VERSION 5.7 ;
  NOWIREEXTENSIONATPIN ON ;
  DIVIDERCHAR "/" ;
  BUSBITCHARS "[]" ;
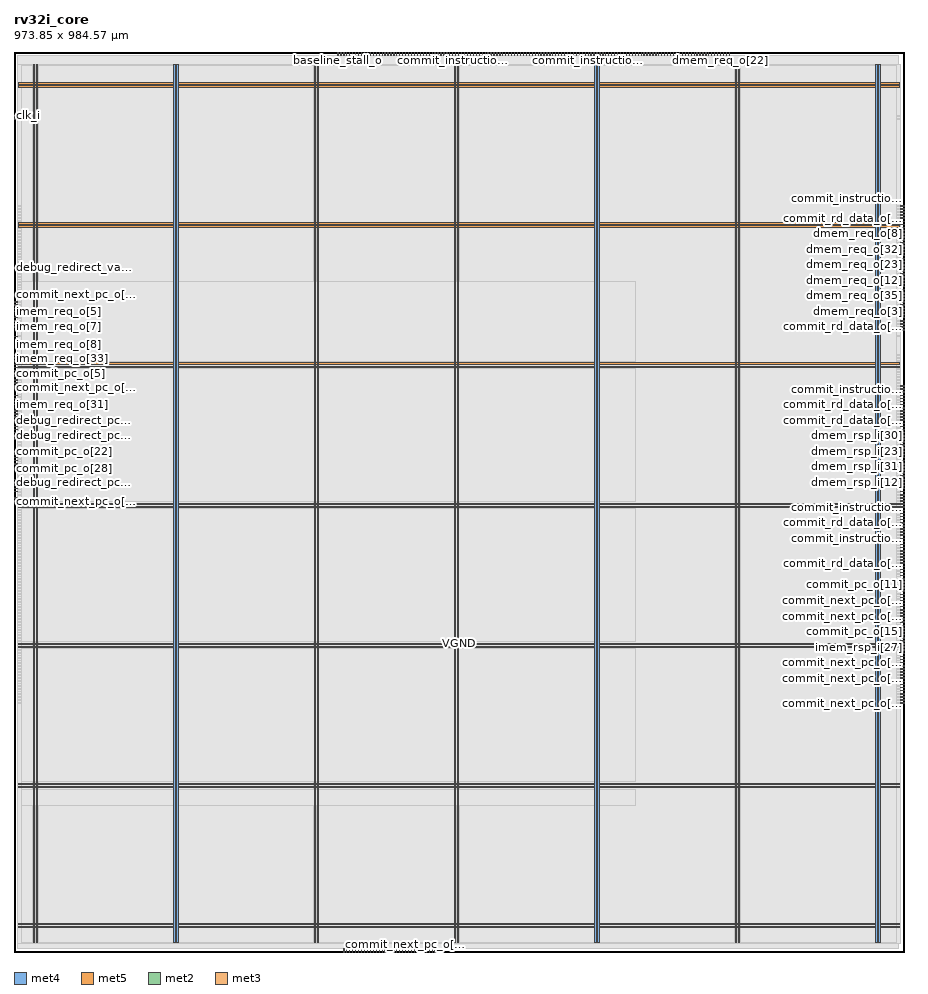
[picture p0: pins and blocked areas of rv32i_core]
MACRO rv32i_core
  CLASS BLOCK ;
  FOREIGN rv32i_core ;
  ORIGIN 0.000 0.000 ;
  SIZE 973.850 BY 984.570 ;
  PIN VGND
    DIRECTION INOUT ;
    USE GROUND ;
    PORT
      LAYER met4 ;
        RECT 24.340 10.640 25.940 971.280 ;
    END
    PORT
      LAYER met4 ;
        RECT 177.940 10.640 179.540 971.280 ;
    END
    PORT
      LAYER met4 ;
        RECT 331.540 10.640 333.140 971.280 ;
    END
    PORT
      LAYER met4 ;
        RECT 485.140 10.640 486.740 971.280 ;
    END
    PORT
      LAYER met4 ;
        RECT 638.740 10.640 640.340 971.280 ;
    END
    PORT
      LAYER met4 ;
        RECT 792.340 10.640 793.940 971.280 ;
    END
    PORT
      LAYER met4 ;
        RECT 945.940 10.640 947.540 971.280 ;
    END
    PORT
      LAYER met5 ;
        RECT 5.280 30.030 968.540 31.630 ;
    END
    PORT
      LAYER met5 ;
        RECT 5.280 183.210 968.540 184.810 ;
    END
    PORT
      LAYER met5 ;
        RECT 5.280 336.390 968.540 337.990 ;
    END
    PORT
      LAYER met5 ;
        RECT 5.280 489.570 968.540 491.170 ;
    END
    PORT
      LAYER met5 ;
        RECT 5.280 642.750 968.540 644.350 ;
    END
    PORT
      LAYER met5 ;
        RECT 5.280 795.930 968.540 797.530 ;
    END
    PORT
      LAYER met5 ;
        RECT 5.280 949.110 968.540 950.710 ;
    END
  END VGND
  PIN VPWR
    DIRECTION INOUT ;
    USE POWER ;
    PORT
      LAYER met4 ;
        RECT 21.040 10.640 22.640 971.280 ;
    END
    PORT
      LAYER met4 ;
        RECT 174.640 10.640 176.240 971.280 ;
    END
    PORT
      LAYER met4 ;
        RECT 328.240 10.640 329.840 971.280 ;
    END
    PORT
      LAYER met4 ;
        RECT 481.840 10.640 483.440 971.280 ;
    END
    PORT
      LAYER met4 ;
        RECT 635.440 10.640 637.040 971.280 ;
    END
    PORT
      LAYER met4 ;
        RECT 789.040 10.640 790.640 971.280 ;
    END
    PORT
      LAYER met4 ;
        RECT 942.640 10.640 944.240 971.280 ;
    END
    PORT
      LAYER met5 ;
        RECT 5.280 26.730 968.540 28.330 ;
    END
    PORT
      LAYER met5 ;
        RECT 5.280 179.910 968.540 181.510 ;
    END
    PORT
      LAYER met5 ;
        RECT 5.280 333.090 968.540 334.690 ;
    END
    PORT
      LAYER met5 ;
        RECT 5.280 486.270 968.540 487.870 ;
    END
    PORT
      LAYER met5 ;
        RECT 5.280 639.450 968.540 641.050 ;
    END
    PORT
      LAYER met5 ;
        RECT 5.280 792.630 968.540 794.230 ;
    END
    PORT
      LAYER met5 ;
        RECT 5.280 945.810 968.540 947.410 ;
    END
  END VPWR
  PIN baseline_stall_o
    DIRECTION OUTPUT ;
    USE SIGNAL ;
    ANTENNADIFFAREA 0.340600 ;
    PORT
      LAYER met2 ;
        RECT 354.290 980.570 354.570 984.570 ;
    END
  END baseline_stall_o
  PIN clk_i
    DIRECTION INPUT ;
    USE SIGNAL ;
    ANTENNAGATEAREA 1.286700 ;
    ANTENNADIFFAREA 0.434700 ;
    PORT
      LAYER met3 ;
        RECT 0.000 914.640 4.000 915.240 ;
    END
  END clk_i
  PIN commit_instruction_o[0]
    DIRECTION OUTPUT ;
    USE SIGNAL ;
    ANTENNADIFFAREA 0.340600 ;
    PORT
      LAYER met2 ;
        RECT 627.990 980.570 628.270 984.570 ;
    END
  END commit_instruction_o[0]
  PIN commit_instruction_o[10]
    DIRECTION OUTPUT ;
    USE SIGNAL ;
    ANTENNADIFFAREA 0.340600 ;
    PORT
      LAYER met3 ;
        RECT 969.850 615.440 973.850 616.040 ;
    END
  END commit_instruction_o[10]
  PIN commit_instruction_o[11]
    DIRECTION OUTPUT ;
    USE SIGNAL ;
    ANTENNADIFFAREA 0.340600 ;
    PORT
      LAYER met3 ;
        RECT 969.850 816.040 973.850 816.640 ;
    END
  END commit_instruction_o[11]
  PIN commit_instruction_o[12]
    DIRECTION OUTPUT ;
    USE SIGNAL ;
    ANTENNADIFFAREA 0.340600 ;
    PORT
      LAYER met2 ;
        RECT 618.330 980.570 618.610 984.570 ;
    END
  END commit_instruction_o[12]
  PIN commit_instruction_o[13]
    DIRECTION OUTPUT ;
    USE SIGNAL ;
    ANTENNADIFFAREA 0.340600 ;
    PORT
      LAYER met3 ;
        RECT 969.850 506.640 973.850 507.240 ;
    END
  END commit_instruction_o[13]
  PIN commit_instruction_o[14]
    DIRECTION OUTPUT ;
    USE SIGNAL ;
    ANTENNADIFFAREA 0.340600 ;
    PORT
      LAYER met3 ;
        RECT 969.850 496.440 973.850 497.040 ;
    END
  END commit_instruction_o[14]
  PIN commit_instruction_o[15]
    DIRECTION OUTPUT ;
    USE SIGNAL ;
    ANTENNADIFFAREA 0.340600 ;
    PORT
      LAYER met3 ;
        RECT 969.850 445.440 973.850 446.040 ;
    END
  END commit_instruction_o[15]
  PIN commit_instruction_o[16]
    DIRECTION OUTPUT ;
    USE SIGNAL ;
    ANTENNADIFFAREA 0.340600 ;
    PORT
      LAYER met3 ;
        RECT 969.850 452.240 973.850 452.840 ;
    END
  END commit_instruction_o[16]
  PIN commit_instruction_o[17]
    DIRECTION OUTPUT ;
    USE SIGNAL ;
    ANTENNADIFFAREA 0.340600 ;
    PORT
      LAYER met3 ;
        RECT 969.850 486.240 973.850 486.840 ;
    END
  END commit_instruction_o[17]
  PIN commit_instruction_o[18]
    DIRECTION OUTPUT ;
    USE SIGNAL ;
    ANTENNADIFFAREA 0.340600 ;
    PORT
      LAYER met3 ;
        RECT 969.850 431.840 973.850 432.440 ;
    END
  END commit_instruction_o[18]
  PIN commit_instruction_o[19]
    DIRECTION OUTPUT ;
    USE SIGNAL ;
    ANTENNADIFFAREA 0.340600 ;
    PORT
      LAYER met3 ;
        RECT 969.850 459.040 973.850 459.640 ;
    END
  END commit_instruction_o[19]
  PIN commit_instruction_o[1]
    DIRECTION OUTPUT ;
    USE SIGNAL ;
    ANTENNADIFFAREA 0.340600 ;
    PORT
      LAYER met2 ;
        RECT 611.890 980.570 612.170 984.570 ;
    END
  END commit_instruction_o[1]
  PIN commit_instruction_o[20]
    DIRECTION OUTPUT ;
    USE SIGNAL ;
    ANTENNADIFFAREA 0.340600 ;
    PORT
      LAYER met2 ;
        RECT 363.950 980.570 364.230 984.570 ;
    END
  END commit_instruction_o[20]
  PIN commit_instruction_o[21]
    DIRECTION OUTPUT ;
    USE SIGNAL ;
    ANTENNADIFFAREA 0.340600 ;
    PORT
      LAYER met2 ;
        RECT 547.490 980.570 547.770 984.570 ;
    END
  END commit_instruction_o[21]
  PIN commit_instruction_o[22]
    DIRECTION OUTPUT ;
    USE SIGNAL ;
    ANTENNADIFFAREA 0.340600 ;
    PORT
      LAYER met2 ;
        RECT 502.410 980.570 502.690 984.570 ;
    END
  END commit_instruction_o[22]
  PIN commit_instruction_o[23]
    DIRECTION OUTPUT ;
    USE SIGNAL ;
    ANTENNADIFFAREA 0.340600 ;
    PORT
      LAYER met2 ;
        RECT 505.630 980.570 505.910 984.570 ;
    END
  END commit_instruction_o[23]
  PIN commit_instruction_o[24]
    DIRECTION OUTPUT ;
    USE SIGNAL ;
    ANTENNADIFFAREA 0.340600 ;
    PORT
      LAYER met2 ;
        RECT 508.850 980.570 509.130 984.570 ;
    END
  END commit_instruction_o[24]
  PIN commit_instruction_o[25]
    DIRECTION OUTPUT ;
    USE SIGNAL ;
    ANTENNADIFFAREA 0.340600 ;
    PORT
      LAYER met2 ;
        RECT 380.050 980.570 380.330 984.570 ;
    END
  END commit_instruction_o[25]
  PIN commit_instruction_o[26]
    DIRECTION OUTPUT ;
    USE SIGNAL ;
    ANTENNADIFFAREA 0.340600 ;
    PORT
      LAYER met2 ;
        RECT 479.870 980.570 480.150 984.570 ;
    END
  END commit_instruction_o[26]
  PIN commit_instruction_o[27]
    DIRECTION OUTPUT ;
    USE SIGNAL ;
    ANTENNADIFFAREA 0.340600 ;
    PORT
      LAYER met2 ;
        RECT 418.690 980.570 418.970 984.570 ;
    END
  END commit_instruction_o[27]
  PIN commit_instruction_o[28]
    DIRECTION OUTPUT ;
    USE SIGNAL ;
    ANTENNADIFFAREA 0.340600 ;
    PORT
      LAYER met2 ;
        RECT 476.650 980.570 476.930 984.570 ;
    END
  END commit_instruction_o[28]
  PIN commit_instruction_o[29]
    DIRECTION OUTPUT ;
    USE SIGNAL ;
    ANTENNADIFFAREA 0.340600 ;
    PORT
      LAYER met2 ;
        RECT 444.450 980.570 444.730 984.570 ;
    END
  END commit_instruction_o[29]
  PIN commit_instruction_o[2]
    DIRECTION OUTPUT ;
    USE SIGNAL ;
    ANTENNADIFFAREA 0.340600 ;
    PORT
      LAYER met2 ;
        RECT 615.110 980.570 615.390 984.570 ;
    END
  END commit_instruction_o[2]
  PIN commit_instruction_o[30]
    DIRECTION OUTPUT ;
    USE SIGNAL ;
    ANTENNADIFFAREA 0.340600 ;
    PORT
      LAYER met2 ;
        RECT 447.670 980.570 447.950 984.570 ;
    END
  END commit_instruction_o[30]
  PIN commit_instruction_o[31]
    DIRECTION OUTPUT ;
    USE SIGNAL ;
    ANTENNADIFFAREA 0.340600 ;
    PORT
      LAYER met2 ;
        RECT 434.790 980.570 435.070 984.570 ;
    END
  END commit_instruction_o[31]
  PIN commit_instruction_o[3]
    DIRECTION OUTPUT ;
    USE SIGNAL ;
    ANTENNADIFFAREA 0.340600 ;
    PORT
      LAYER met2 ;
        RECT 483.090 980.570 483.370 984.570 ;
    END
  END commit_instruction_o[3]
  PIN commit_instruction_o[4]
    DIRECTION OUTPUT ;
    USE SIGNAL ;
    ANTENNADIFFAREA 0.340600 ;
    PORT
      LAYER met2 ;
        RECT 473.430 980.570 473.710 984.570 ;
    END
  END commit_instruction_o[4]
  PIN commit_instruction_o[5]
    DIRECTION OUTPUT ;
    USE SIGNAL ;
    ANTENNADIFFAREA 0.340600 ;
    PORT
      LAYER met2 ;
        RECT 499.190 980.570 499.470 984.570 ;
    END
  END commit_instruction_o[5]
  PIN commit_instruction_o[6]
    DIRECTION OUTPUT ;
    USE SIGNAL ;
    ANTENNADIFFAREA 0.340600 ;
    PORT
      LAYER met2 ;
        RECT 489.530 980.570 489.810 984.570 ;
    END
  END commit_instruction_o[6]
  PIN commit_instruction_o[7]
    DIRECTION OUTPUT ;
    USE SIGNAL ;
    ANTENNADIFFAREA 0.340600 ;
    PORT
      LAYER met3 ;
        RECT 969.850 775.240 973.850 775.840 ;
    END
  END commit_instruction_o[7]
  PIN commit_instruction_o[8]
    DIRECTION OUTPUT ;
    USE SIGNAL ;
    ANTENNADIFFAREA 0.340600 ;
    PORT
      LAYER met3 ;
        RECT 969.850 754.840 973.850 755.440 ;
    END
  END commit_instruction_o[8]
  PIN commit_instruction_o[9]
    DIRECTION OUTPUT ;
    USE SIGNAL ;
    ANTENNADIFFAREA 0.340600 ;
    PORT
      LAYER met3 ;
        RECT 969.850 584.840 973.850 585.440 ;
    END
  END commit_instruction_o[9]
  PIN commit_next_pc_o[0]
    DIRECTION OUTPUT ;
    USE SIGNAL ;
    ANTENNADIFFAREA 0.340600 ;
    PORT
      LAYER met2 ;
        RECT 466.990 980.570 467.270 984.570 ;
    END
  END commit_next_pc_o[0]
  PIN commit_next_pc_o[10]
    DIRECTION OUTPUT ;
    USE SIGNAL ;
    ANTENNADIFFAREA 0.340600 ;
    PORT
      LAYER met2 ;
        RECT 383.270 980.570 383.550 984.570 ;
    END
  END commit_next_pc_o[10]
  PIN commit_next_pc_o[11]
    DIRECTION OUTPUT ;
    USE SIGNAL ;
    ANTENNADIFFAREA 0.340600 ;
    PORT
      LAYER met3 ;
        RECT 969.850 272.040 973.850 272.640 ;
    END
  END commit_next_pc_o[11]
  PIN commit_next_pc_o[12]
    DIRECTION OUTPUT ;
    USE SIGNAL ;
    ANTENNADIFFAREA 0.340600 ;
    PORT
      LAYER met2 ;
        RECT 521.730 980.570 522.010 984.570 ;
    END
  END commit_next_pc_o[12]
  PIN commit_next_pc_o[13]
    DIRECTION OUTPUT ;
    USE SIGNAL ;
    ANTENNADIFFAREA 0.340600 ;
    PORT
      LAYER met2 ;
        RECT 376.830 980.570 377.110 984.570 ;
    END
  END commit_next_pc_o[13]
  PIN commit_next_pc_o[14]
    DIRECTION OUTPUT ;
    USE SIGNAL ;
    ANTENNADIFFAREA 0.340600 ;
    PORT
      LAYER met3 ;
        RECT 0.000 652.840 4.000 653.440 ;
    END
  END commit_next_pc_o[14]
  PIN commit_next_pc_o[15]
    DIRECTION OUTPUT ;
    USE SIGNAL ;
    ANTENNADIFFAREA 0.340600 ;
    PORT
      LAYER met3 ;
        RECT 969.850 275.440 973.850 276.040 ;
    END
  END commit_next_pc_o[15]
  PIN commit_next_pc_o[16]
    DIRECTION OUTPUT ;
    USE SIGNAL ;
    ANTENNADIFFAREA 0.340600 ;
    PORT
      LAYER met2 ;
        RECT 553.930 980.570 554.210 984.570 ;
    END
  END commit_next_pc_o[16]
  PIN commit_next_pc_o[17]
    DIRECTION OUTPUT ;
    USE SIGNAL ;
    ANTENNADIFFAREA 0.340600 ;
    PORT
      LAYER met2 ;
        RECT 524.950 980.570 525.230 984.570 ;
    END
  END commit_next_pc_o[17]
  PIN commit_next_pc_o[18]
    DIRECTION OUTPUT ;
    USE SIGNAL ;
    ANTENNADIFFAREA 0.340600 ;
    PORT
      LAYER met3 ;
        RECT 969.850 299.240 973.850 299.840 ;
    END
  END commit_next_pc_o[18]
  PIN commit_next_pc_o[19]
    DIRECTION OUTPUT ;
    USE SIGNAL ;
    ANTENNADIFFAREA 0.340600 ;
    PORT
      LAYER met2 ;
        RECT 428.350 0.000 428.630 4.000 ;
    END
  END commit_next_pc_o[19]
  PIN commit_next_pc_o[1]
    DIRECTION OUTPUT ;
    USE SIGNAL ;
    ANTENNADIFFAREA 0.340600 ;
    PORT
      LAYER met2 ;
        RECT 566.810 980.570 567.090 984.570 ;
    END
  END commit_next_pc_o[1]
  PIN commit_next_pc_o[20]
    DIRECTION OUTPUT ;
    USE SIGNAL ;
    ANTENNADIFFAREA 0.340600 ;
    PORT
      LAYER met2 ;
        RECT 515.290 980.570 515.570 984.570 ;
    END
  END commit_next_pc_o[20]
  PIN commit_next_pc_o[21]
    DIRECTION OUTPUT ;
    USE SIGNAL ;
    ANTENNADIFFAREA 0.340600 ;
    PORT
      LAYER met2 ;
        RECT 531.390 980.570 531.670 984.570 ;
    END
  END commit_next_pc_o[21]
  PIN commit_next_pc_o[22]
    DIRECTION OUTPUT ;
    USE SIGNAL ;
    ANTENNADIFFAREA 0.340600 ;
    PORT
      LAYER met2 ;
        RECT 389.710 980.570 389.990 984.570 ;
    END
  END commit_next_pc_o[22]
  PIN commit_next_pc_o[23]
    DIRECTION OUTPUT ;
    USE SIGNAL ;
    ANTENNADIFFAREA 0.340600 ;
    PORT
      LAYER met2 ;
        RECT 592.570 980.570 592.850 984.570 ;
    END
  END commit_next_pc_o[23]
  PIN commit_next_pc_o[24]
    DIRECTION OUTPUT ;
    USE SIGNAL ;
    ANTENNADIFFAREA 0.340600 ;
    PORT
      LAYER met2 ;
        RECT 425.130 980.570 425.410 984.570 ;
    END
  END commit_next_pc_o[24]
  PIN commit_next_pc_o[25]
    DIRECTION OUTPUT ;
    USE SIGNAL ;
    ANTENNADIFFAREA 0.340600 ;
    PORT
      LAYER met3 ;
        RECT 0.000 710.640 4.000 711.240 ;
    END
  END commit_next_pc_o[25]
  PIN commit_next_pc_o[26]
    DIRECTION OUTPUT ;
    USE SIGNAL ;
    ANTENNADIFFAREA 0.340600 ;
    PORT
      LAYER met3 ;
        RECT 969.850 316.240 973.850 316.840 ;
    END
  END commit_next_pc_o[26]
  PIN commit_next_pc_o[27]
    DIRECTION OUTPUT ;
    USE SIGNAL ;
    ANTENNADIFFAREA 0.340600 ;
    PORT
      LAYER met2 ;
        RECT 454.110 980.570 454.390 984.570 ;
    END
  END commit_next_pc_o[27]
  PIN commit_next_pc_o[28]
    DIRECTION OUTPUT ;
    USE SIGNAL ;
    ANTENNADIFFAREA 0.340600 ;
    PORT
      LAYER met2 ;
        RECT 367.170 980.570 367.450 984.570 ;
    END
  END commit_next_pc_o[28]
  PIN commit_next_pc_o[29]
    DIRECTION OUTPUT ;
    USE SIGNAL ;
    ANTENNADIFFAREA 0.340600 ;
    PORT
      LAYER met3 ;
        RECT 969.850 346.840 973.850 347.440 ;
    END
  END commit_next_pc_o[29]
  PIN commit_next_pc_o[2]
    DIRECTION OUTPUT ;
    USE SIGNAL ;
    ANTENNADIFFAREA 0.340600 ;
    PORT
      LAYER met3 ;
        RECT 969.850 306.040 973.850 306.640 ;
    END
  END commit_next_pc_o[2]
  PIN commit_next_pc_o[30]
    DIRECTION OUTPUT ;
    USE SIGNAL ;
    ANTENNADIFFAREA 0.340600 ;
    PORT
      LAYER met2 ;
        RECT 541.050 980.570 541.330 984.570 ;
    END
  END commit_next_pc_o[30]
  PIN commit_next_pc_o[31]
    DIRECTION OUTPUT ;
    USE SIGNAL ;
    ANTENNADIFFAREA 0.340600 ;
    PORT
      LAYER met3 ;
        RECT 969.850 367.240 973.850 367.840 ;
    END
  END commit_next_pc_o[31]
  PIN commit_next_pc_o[3]
    DIRECTION OUTPUT ;
    USE SIGNAL ;
    ANTENNADIFFAREA 0.340600 ;
    PORT
      LAYER met3 ;
        RECT 0.000 493.040 4.000 493.640 ;
    END
  END commit_next_pc_o[3]
  PIN commit_next_pc_o[4]
    DIRECTION OUTPUT ;
    USE SIGNAL ;
    ANTENNADIFFAREA 0.340600 ;
    PORT
      LAYER met2 ;
        RECT 560.370 980.570 560.650 984.570 ;
    END
  END commit_next_pc_o[4]
  PIN commit_next_pc_o[5]
    DIRECTION OUTPUT ;
    USE SIGNAL ;
    ANTENNADIFFAREA 0.340600 ;
    PORT
      LAYER met3 ;
        RECT 969.850 472.640 973.850 473.240 ;
    END
  END commit_next_pc_o[5]
  PIN commit_next_pc_o[6]
    DIRECTION OUTPUT ;
    USE SIGNAL ;
    ANTENNADIFFAREA 0.340600 ;
    PORT
      LAYER met2 ;
        RECT 392.930 980.570 393.210 984.570 ;
    END
  END commit_next_pc_o[6]
  PIN commit_next_pc_o[7]
    DIRECTION OUTPUT ;
    USE SIGNAL ;
    ANTENNADIFFAREA 0.340600 ;
    PORT
      LAYER met3 ;
        RECT 0.000 608.640 4.000 609.240 ;
    END
  END commit_next_pc_o[7]
  PIN commit_next_pc_o[8]
    DIRECTION OUTPUT ;
    USE SIGNAL ;
    ANTENNADIFFAREA 0.340600 ;
    PORT
      LAYER met3 ;
        RECT 969.850 384.240 973.850 384.840 ;
    END
  END commit_next_pc_o[8]
  PIN commit_next_pc_o[9]
    DIRECTION OUTPUT ;
    USE SIGNAL ;
    ANTENNADIFFAREA 0.340600 ;
    PORT
      LAYER met3 ;
        RECT 0.000 690.240 4.000 690.840 ;
    END
  END commit_next_pc_o[9]
  PIN commit_pc_o[0]
    DIRECTION OUTPUT ;
    USE SIGNAL ;
    ANTENNADIFFAREA 0.340600 ;
    PORT
      LAYER met2 ;
        RECT 650.530 980.570 650.810 984.570 ;
    END
  END commit_pc_o[0]
  PIN commit_pc_o[10]
    DIRECTION OUTPUT ;
    USE SIGNAL ;
    ANTENNADIFFAREA 0.340600 ;
    PORT
      LAYER met3 ;
        RECT 969.850 374.040 973.850 374.640 ;
    END
  END commit_pc_o[10]
  PIN commit_pc_o[11]
    DIRECTION OUTPUT ;
    USE SIGNAL ;
    ANTENNADIFFAREA 0.340600 ;
    PORT
      LAYER met3 ;
        RECT 969.850 401.240 973.850 401.840 ;
    END
  END commit_pc_o[11]
  PIN commit_pc_o[12]
    DIRECTION OUTPUT ;
    USE SIGNAL ;
    ANTENNADIFFAREA 0.340600 ;
    PORT
      LAYER met3 ;
        RECT 969.850 448.840 973.850 449.440 ;
    END
  END commit_pc_o[12]
  PIN commit_pc_o[13]
    DIRECTION OUTPUT ;
    USE SIGNAL ;
    ANTENNADIFFAREA 0.340600 ;
    PORT
      LAYER met2 ;
        RECT 454.110 0.000 454.390 4.000 ;
    END
  END commit_pc_o[13]
  PIN commit_pc_o[14]
    DIRECTION OUTPUT ;
    USE SIGNAL ;
    ANTENNADIFFAREA 0.340600 ;
    PORT
      LAYER met3 ;
        RECT 969.850 465.840 973.850 466.440 ;
    END
  END commit_pc_o[14]
  PIN commit_pc_o[15]
    DIRECTION OUTPUT ;
    USE SIGNAL ;
    ANTENNADIFFAREA 0.340600 ;
    PORT
      LAYER met3 ;
        RECT 969.850 350.240 973.850 350.840 ;
    END
  END commit_pc_o[15]
  PIN commit_pc_o[16]
    DIRECTION OUTPUT ;
    USE SIGNAL ;
    ANTENNADIFFAREA 0.340600 ;
    PORT
      LAYER met3 ;
        RECT 969.850 357.040 973.850 357.640 ;
    END
  END commit_pc_o[16]
  PIN commit_pc_o[17]
    DIRECTION OUTPUT ;
    USE SIGNAL ;
    ANTENNADIFFAREA 0.340600 ;
    PORT
      LAYER met3 ;
        RECT 969.850 391.040 973.850 391.640 ;
    END
  END commit_pc_o[17]
  PIN commit_pc_o[18]
    DIRECTION OUTPUT ;
    USE SIGNAL ;
    ANTENNADIFFAREA 0.340600 ;
    PORT
      LAYER met3 ;
        RECT 969.850 387.640 973.850 388.240 ;
    END
  END commit_pc_o[18]
  PIN commit_pc_o[19]
    DIRECTION OUTPUT ;
    USE SIGNAL ;
    ANTENNADIFFAREA 0.340600 ;
    PORT
      LAYER met3 ;
        RECT 969.850 302.640 973.850 303.240 ;
    END
  END commit_pc_o[19]
  PIN commit_pc_o[1]
    DIRECTION OUTPUT ;
    USE SIGNAL ;
    ANTENNADIFFAREA 0.340600 ;
    PORT
      LAYER met2 ;
        RECT 599.010 980.570 599.290 984.570 ;
    END
  END commit_pc_o[1]
  PIN commit_pc_o[20]
    DIRECTION OUTPUT ;
    USE SIGNAL ;
    ANTENNADIFFAREA 0.340600 ;
    PORT
      LAYER met3 ;
        RECT 0.000 506.640 4.000 507.240 ;
    END
  END commit_pc_o[20]
  PIN commit_pc_o[21]
    DIRECTION OUTPUT ;
    USE SIGNAL ;
    ANTENNADIFFAREA 0.340600 ;
    PORT
      LAYER met3 ;
        RECT 0.000 567.840 4.000 568.440 ;
    END
  END commit_pc_o[21]
  PIN commit_pc_o[22]
    DIRECTION OUTPUT ;
    USE SIGNAL ;
    ANTENNADIFFAREA 0.340600 ;
    PORT
      LAYER met3 ;
        RECT 0.000 547.440 4.000 548.040 ;
    END
  END commit_pc_o[22]
  PIN commit_pc_o[23]
    DIRECTION OUTPUT ;
    USE SIGNAL ;
    ANTENNADIFFAREA 0.340600 ;
    PORT
      LAYER met3 ;
        RECT 969.850 360.440 973.850 361.040 ;
    END
  END commit_pc_o[23]
  PIN commit_pc_o[24]
    DIRECTION OUTPUT ;
    USE SIGNAL ;
    ANTENNADIFFAREA 0.340600 ;
    PORT
      LAYER met3 ;
        RECT 0.000 496.440 4.000 497.040 ;
    END
  END commit_pc_o[24]
  PIN commit_pc_o[25]
    DIRECTION OUTPUT ;
    USE SIGNAL ;
    ANTENNADIFFAREA 0.340600 ;
    PORT
      LAYER met3 ;
        RECT 0.000 533.840 4.000 534.440 ;
    END
  END commit_pc_o[25]
  PIN commit_pc_o[26]
    DIRECTION OUTPUT ;
    USE SIGNAL ;
    ANTENNADIFFAREA 0.340600 ;
    PORT
      LAYER met2 ;
        RECT 444.450 0.000 444.730 4.000 ;
    END
  END commit_pc_o[26]
  PIN commit_pc_o[27]
    DIRECTION OUTPUT ;
    USE SIGNAL ;
    ANTENNADIFFAREA 0.340600 ;
    PORT
      LAYER met3 ;
        RECT 0.000 516.840 4.000 517.440 ;
    END
  END commit_pc_o[27]
  PIN commit_pc_o[28]
    DIRECTION OUTPUT ;
    USE SIGNAL ;
    ANTENNADIFFAREA 0.340600 ;
    PORT
      LAYER met3 ;
        RECT 0.000 537.240 4.000 537.840 ;
    END
  END commit_pc_o[28]
  PIN commit_pc_o[29]
    DIRECTION OUTPUT ;
    USE SIGNAL ;
    ANTENNADIFFAREA 0.340600 ;
    PORT
      LAYER met3 ;
        RECT 969.850 397.840 973.850 398.440 ;
    END
  END commit_pc_o[29]
  PIN commit_pc_o[2]
    DIRECTION OUTPUT ;
    USE SIGNAL ;
    ANTENNADIFFAREA 0.340600 ;
    PORT
      LAYER met2 ;
        RECT 470.210 980.570 470.490 984.570 ;
    END
  END commit_pc_o[2]
  PIN commit_pc_o[30]
    DIRECTION OUTPUT ;
    USE SIGNAL ;
    ANTENNADIFFAREA 0.340600 ;
    PORT
      LAYER met3 ;
        RECT 0.000 601.840 4.000 602.440 ;
    END
  END commit_pc_o[30]
  PIN commit_pc_o[31]
    DIRECTION OUTPUT ;
    USE SIGNAL ;
    ANTENNADIFFAREA 0.340600 ;
    PORT
      LAYER met2 ;
        RECT 457.330 0.000 457.610 4.000 ;
    END
  END commit_pc_o[31]
  PIN commit_pc_o[3]
    DIRECTION OUTPUT ;
    USE SIGNAL ;
    ANTENNADIFFAREA 0.340600 ;
    PORT
      LAYER met3 ;
        RECT 0.000 646.040 4.000 646.640 ;
    END
  END commit_pc_o[3]
  PIN commit_pc_o[4]
    DIRECTION OUTPUT ;
    USE SIGNAL ;
    ANTENNADIFFAREA 0.340600 ;
    PORT
      LAYER met3 ;
        RECT 0.000 639.240 4.000 639.840 ;
    END
  END commit_pc_o[4]
  PIN commit_pc_o[5]
    DIRECTION OUTPUT ;
    USE SIGNAL ;
    ANTENNADIFFAREA 0.340600 ;
    PORT
      LAYER met3 ;
        RECT 0.000 632.440 4.000 633.040 ;
    END
  END commit_pc_o[5]
  PIN commit_pc_o[6]
    DIRECTION OUTPUT ;
    USE SIGNAL ;
    ANTENNADIFFAREA 0.340600 ;
    PORT
      LAYER met3 ;
        RECT 0.000 635.840 4.000 636.440 ;
    END
  END commit_pc_o[6]
  PIN commit_pc_o[7]
    DIRECTION OUTPUT ;
    USE SIGNAL ;
    ANTENNADIFFAREA 0.340600 ;
    PORT
      LAYER met3 ;
        RECT 0.000 642.640 4.000 643.240 ;
    END
  END commit_pc_o[7]
  PIN commit_pc_o[8]
    DIRECTION OUTPUT ;
    USE SIGNAL ;
    ANTENNADIFFAREA 0.340600 ;
    PORT
      LAYER met3 ;
        RECT 969.850 377.440 973.850 378.040 ;
    END
  END commit_pc_o[8]
  PIN commit_pc_o[9]
    DIRECTION OUTPUT ;
    USE SIGNAL ;
    ANTENNADIFFAREA 0.340600 ;
    PORT
      LAYER met3 ;
        RECT 969.850 394.440 973.850 395.040 ;
    END
  END commit_pc_o[9]
  PIN commit_rd_data_o[0]
    DIRECTION OUTPUT ;
    USE SIGNAL ;
    ANTENNADIFFAREA 0.340600 ;
    PORT
      LAYER met3 ;
        RECT 969.850 802.440 973.850 803.040 ;
    END
  END commit_rd_data_o[0]
  PIN commit_rd_data_o[10]
    DIRECTION OUTPUT ;
    USE SIGNAL ;
    ANTENNADIFFAREA 0.340600 ;
    PORT
      LAYER met3 ;
        RECT 969.850 601.840 973.850 602.440 ;
    END
  END commit_rd_data_o[10]
  PIN commit_rd_data_o[11]
    DIRECTION OUTPUT ;
    USE SIGNAL ;
    ANTENNADIFFAREA 0.340600 ;
    PORT
      LAYER met3 ;
        RECT 969.850 289.040 973.850 289.640 ;
    END
  END commit_rd_data_o[11]
  PIN commit_rd_data_o[12]
    DIRECTION OUTPUT ;
    USE SIGNAL ;
    ANTENNADIFFAREA 0.340600 ;
    PORT
      LAYER met3 ;
        RECT 969.850 595.040 973.850 595.640 ;
    END
  END commit_rd_data_o[12]
  PIN commit_rd_data_o[13]
    DIRECTION OUTPUT ;
    USE SIGNAL ;
    ANTENNADIFFAREA 0.340600 ;
    PORT
      LAYER met3 ;
        RECT 969.850 295.840 973.850 296.440 ;
    END
  END commit_rd_data_o[13]
  PIN commit_rd_data_o[14]
    DIRECTION OUTPUT ;
    USE SIGNAL ;
    ANTENNADIFFAREA 0.340600 ;
    PORT
      LAYER met3 ;
        RECT 969.850 425.040 973.850 425.640 ;
    END
  END commit_rd_data_o[14]
  PIN commit_rd_data_o[15]
    DIRECTION OUTPUT ;
    USE SIGNAL ;
    ANTENNADIFFAREA 0.340600 ;
    PORT
      LAYER met3 ;
        RECT 969.850 455.640 973.850 456.240 ;
    END
  END commit_rd_data_o[15]
  PIN commit_rd_data_o[16]
    DIRECTION OUTPUT ;
    USE SIGNAL ;
    ANTENNADIFFAREA 0.340600 ;
    PORT
      LAYER met3 ;
        RECT 969.850 411.440 973.850 412.040 ;
    END
  END commit_rd_data_o[16]
  PIN commit_rd_data_o[17]
    DIRECTION OUTPUT ;
    USE SIGNAL ;
    ANTENNADIFFAREA 0.340600 ;
    PORT
      LAYER met3 ;
        RECT 969.850 795.640 973.850 796.240 ;
    END
  END commit_rd_data_o[17]
  PIN commit_rd_data_o[18]
    DIRECTION OUTPUT ;
    USE SIGNAL ;
    ANTENNADIFFAREA 0.340600 ;
    PORT
      LAYER met3 ;
        RECT 969.850 799.040 973.850 799.640 ;
    END
  END commit_rd_data_o[18]
  PIN commit_rd_data_o[19]
    DIRECTION OUTPUT ;
    USE SIGNAL ;
    ANTENNADIFFAREA 0.340600 ;
    PORT
      LAYER met3 ;
        RECT 969.850 581.440 973.850 582.040 ;
    END
  END commit_rd_data_o[19]
  PIN commit_rd_data_o[1]
    DIRECTION OUTPUT ;
    USE SIGNAL ;
    ANTENNADIFFAREA 0.340600 ;
    PORT
      LAYER met3 ;
        RECT 969.850 792.240 973.850 792.840 ;
    END
  END commit_rd_data_o[1]
  PIN commit_rd_data_o[20]
    DIRECTION OUTPUT ;
    USE SIGNAL ;
    ANTENNADIFFAREA 0.340600 ;
    PORT
      LAYER met3 ;
        RECT 969.850 809.240 973.850 809.840 ;
    END
  END commit_rd_data_o[20]
  PIN commit_rd_data_o[21]
    DIRECTION OUTPUT ;
    USE SIGNAL ;
    ANTENNADIFFAREA 0.340600 ;
    PORT
      LAYER met3 ;
        RECT 969.850 489.640 973.850 490.240 ;
    END
  END commit_rd_data_o[21]
  PIN commit_rd_data_o[22]
    DIRECTION OUTPUT ;
    USE SIGNAL ;
    ANTENNADIFFAREA 0.340600 ;
    PORT
      LAYER met3 ;
        RECT 969.850 421.640 973.850 422.240 ;
    END
  END commit_rd_data_o[22]
  PIN commit_rd_data_o[23]
    DIRECTION OUTPUT ;
    USE SIGNAL ;
    ANTENNADIFFAREA 0.340600 ;
    PORT
      LAYER met3 ;
        RECT 969.850 278.840 973.850 279.440 ;
    END
  END commit_rd_data_o[23]
  PIN commit_rd_data_o[24]
    DIRECTION OUTPUT ;
    USE SIGNAL ;
    ANTENNADIFFAREA 0.340600 ;
    PORT
      LAYER met3 ;
        RECT 969.850 363.840 973.850 364.440 ;
    END
  END commit_rd_data_o[24]
  PIN commit_rd_data_o[25]
    DIRECTION OUTPUT ;
    USE SIGNAL ;
    ANTENNADIFFAREA 0.340600 ;
    PORT
      LAYER met3 ;
        RECT 969.850 744.640 973.850 745.240 ;
    END
  END commit_rd_data_o[25]
  PIN commit_rd_data_o[26]
    DIRECTION OUTPUT ;
    USE SIGNAL ;
    ANTENNADIFFAREA 0.340600 ;
    PORT
      LAYER met3 ;
        RECT 969.850 782.040 973.850 782.640 ;
    END
  END commit_rd_data_o[26]
  PIN commit_rd_data_o[27]
    DIRECTION OUTPUT ;
    USE SIGNAL ;
    ANTENNADIFFAREA 0.340600 ;
    PORT
      LAYER met3 ;
        RECT 969.850 540.640 973.850 541.240 ;
    END
  END commit_rd_data_o[27]
  PIN commit_rd_data_o[28]
    DIRECTION OUTPUT ;
    USE SIGNAL ;
    ANTENNADIFFAREA 0.340600 ;
    PORT
      LAYER met3 ;
        RECT 969.850 418.240 973.850 418.840 ;
    END
  END commit_rd_data_o[28]
  PIN commit_rd_data_o[29]
    DIRECTION OUTPUT ;
    USE SIGNAL ;
    ANTENNADIFFAREA 0.340600 ;
    PORT
      LAYER met3 ;
        RECT 969.850 778.640 973.850 779.240 ;
    END
  END commit_rd_data_o[29]
  PIN commit_rd_data_o[2]
    DIRECTION OUTPUT ;
    USE SIGNAL ;
    ANTENNADIFFAREA 0.340600 ;
    PORT
      LAYER met3 ;
        RECT 969.850 683.440 973.850 684.040 ;
    END
  END commit_rd_data_o[2]
  PIN commit_rd_data_o[30]
    DIRECTION OUTPUT ;
    USE SIGNAL ;
    ANTENNADIFFAREA 0.340600 ;
    PORT
      LAYER met3 ;
        RECT 969.850 442.040 973.850 442.640 ;
    END
  END commit_rd_data_o[30]
  PIN commit_rd_data_o[31]
    DIRECTION OUTPUT ;
    USE SIGNAL ;
    ANTENNADIFFAREA 0.340600 ;
    PORT
      LAYER met3 ;
        RECT 969.850 285.640 973.850 286.240 ;
    END
  END commit_rd_data_o[31]
  PIN commit_rd_data_o[3]
    DIRECTION OUTPUT ;
    USE SIGNAL ;
    ANTENNADIFFAREA 0.340600 ;
    PORT
      LAYER met3 ;
        RECT 969.850 510.040 973.850 510.640 ;
    END
  END commit_rd_data_o[3]
  PIN commit_rd_data_o[4]
    DIRECTION OUTPUT ;
    USE SIGNAL ;
    ANTENNADIFFAREA 0.340600 ;
    PORT
      LAYER met3 ;
        RECT 969.850 612.040 973.850 612.640 ;
    END
  END commit_rd_data_o[4]
  PIN commit_rd_data_o[5]
    DIRECTION OUTPUT ;
    USE SIGNAL ;
    ANTENNADIFFAREA 0.340600 ;
    PORT
      LAYER met3 ;
        RECT 969.850 282.240 973.850 282.840 ;
    END
  END commit_rd_data_o[5]
  PIN commit_rd_data_o[6]
    DIRECTION OUTPUT ;
    USE SIGNAL ;
    ANTENNADIFFAREA 0.340600 ;
    PORT
      LAYER met3 ;
        RECT 969.850 309.440 973.850 310.040 ;
    END
  END commit_rd_data_o[6]
  PIN commit_rd_data_o[7]
    DIRECTION OUTPUT ;
    USE SIGNAL ;
    ANTENNADIFFAREA 0.340600 ;
    PORT
      LAYER met3 ;
        RECT 969.850 469.240 973.850 469.840 ;
    END
  END commit_rd_data_o[7]
  PIN commit_rd_data_o[8]
    DIRECTION OUTPUT ;
    USE SIGNAL ;
    ANTENNADIFFAREA 0.340600 ;
    PORT
      LAYER met3 ;
        RECT 969.850 741.240 973.850 741.840 ;
    END
  END commit_rd_data_o[8]
  PIN commit_rd_data_o[9]
    DIRECTION OUTPUT ;
    USE SIGNAL ;
    ANTENNADIFFAREA 0.340600 ;
    PORT
      LAYER met3 ;
        RECT 969.850 598.440 973.850 599.040 ;
    END
  END commit_rd_data_o[9]
  PIN commit_rd_index_o[0]
    DIRECTION OUTPUT ;
    USE SIGNAL ;
    ANTENNADIFFAREA 0.340600 ;
    PORT
      LAYER met3 ;
        RECT 969.850 727.640 973.850 728.240 ;
    END
  END commit_rd_index_o[0]
  PIN commit_rd_index_o[1]
    DIRECTION OUTPUT ;
    USE SIGNAL ;
    ANTENNADIFFAREA 0.340600 ;
    PORT
      LAYER met3 ;
        RECT 969.850 693.640 973.850 694.240 ;
    END
  END commit_rd_index_o[1]
  PIN commit_rd_index_o[2]
    DIRECTION OUTPUT ;
    USE SIGNAL ;
    ANTENNADIFFAREA 0.340600 ;
    PORT
      LAYER met3 ;
        RECT 969.850 578.040 973.850 578.640 ;
    END
  END commit_rd_index_o[2]
  PIN commit_rd_index_o[3]
    DIRECTION OUTPUT ;
    USE SIGNAL ;
    ANTENNADIFFAREA 0.340600 ;
    PORT
      LAYER met3 ;
        RECT 969.850 588.240 973.850 588.840 ;
    END
  END commit_rd_index_o[3]
  PIN commit_rd_index_o[4]
    DIRECTION OUTPUT ;
    USE SIGNAL ;
    ANTENNADIFFAREA 0.340600 ;
    PORT
      LAYER met3 ;
        RECT 969.850 758.240 973.850 758.840 ;
    END
  END commit_rd_index_o[4]
  PIN commit_rd_write_o
    DIRECTION OUTPUT ;
    USE SIGNAL ;
    ANTENNADIFFAREA 0.340600 ;
    PORT
      LAYER met3 ;
        RECT 969.850 788.840 973.850 789.440 ;
    END
  END commit_rd_write_o
  PIN commit_trap_o
    DIRECTION OUTPUT ;
    USE SIGNAL ;
    ANTENNADIFFAREA 0.340600 ;
    PORT
      LAYER met2 ;
        RECT 386.490 980.570 386.770 984.570 ;
    END
  END commit_trap_o
  PIN commit_valid_o
    DIRECTION OUTPUT ;
    USE SIGNAL ;
    ANTENNADIFFAREA 0.340600 ;
    PORT
      LAYER met2 ;
        RECT 405.810 980.570 406.090 984.570 ;
    END
  END commit_valid_o
  PIN debug_redirect_pc_o[0]
    DIRECTION OUTPUT ;
    USE SIGNAL ;
    ANTENNADIFFAREA 0.340600 ;
    PORT
      LAYER met3 ;
        RECT 0.000 686.840 4.000 687.440 ;
    END
  END debug_redirect_pc_o[0]
  PIN debug_redirect_pc_o[10]
    DIRECTION OUTPUT ;
    USE SIGNAL ;
    ANTENNADIFFAREA 0.340600 ;
    PORT
      LAYER met3 ;
        RECT 969.850 438.640 973.850 439.240 ;
    END
  END debug_redirect_pc_o[10]
  PIN debug_redirect_pc_o[11]
    DIRECTION OUTPUT ;
    USE SIGNAL ;
    ANTENNADIFFAREA 0.340600 ;
    PORT
      LAYER met3 ;
        RECT 969.850 435.240 973.850 435.840 ;
    END
  END debug_redirect_pc_o[11]
  PIN debug_redirect_pc_o[12]
    DIRECTION OUTPUT ;
    USE SIGNAL ;
    ANTENNADIFFAREA 0.340600 ;
    PORT
      LAYER met2 ;
        RECT 396.150 0.000 396.430 4.000 ;
    END
  END debug_redirect_pc_o[12]
  PIN debug_redirect_pc_o[13]
    DIRECTION OUTPUT ;
    USE SIGNAL ;
    ANTENNADIFFAREA 0.340600 ;
    PORT
      LAYER met2 ;
        RECT 399.370 0.000 399.650 4.000 ;
    END
  END debug_redirect_pc_o[13]
  PIN debug_redirect_pc_o[14]
    DIRECTION OUTPUT ;
    USE SIGNAL ;
    ANTENNADIFFAREA 0.340600 ;
    PORT
      LAYER met3 ;
        RECT 969.850 479.440 973.850 480.040 ;
    END
  END debug_redirect_pc_o[14]
  PIN debug_redirect_pc_o[15]
    DIRECTION OUTPUT ;
    USE SIGNAL ;
    ANTENNADIFFAREA 0.340600 ;
    PORT
      LAYER met2 ;
        RECT 409.030 0.000 409.310 4.000 ;
    END
  END debug_redirect_pc_o[15]
  PIN debug_redirect_pc_o[16]
    DIRECTION OUTPUT ;
    USE SIGNAL ;
    ANTENNADIFFAREA 0.340600 ;
    PORT
      LAYER met3 ;
        RECT 969.850 414.840 973.850 415.440 ;
    END
  END debug_redirect_pc_o[16]
  PIN debug_redirect_pc_o[17]
    DIRECTION OUTPUT ;
    USE SIGNAL ;
    ANTENNADIFFAREA 0.340600 ;
    PORT
      LAYER met2 ;
        RECT 425.130 0.000 425.410 4.000 ;
    END
  END debug_redirect_pc_o[17]
  PIN debug_redirect_pc_o[18]
    DIRECTION OUTPUT ;
    USE SIGNAL ;
    ANTENNADIFFAREA 0.340600 ;
    PORT
      LAYER met3 ;
        RECT 969.850 404.640 973.850 405.240 ;
    END
  END debug_redirect_pc_o[18]
  PIN debug_redirect_pc_o[19]
    DIRECTION OUTPUT ;
    USE SIGNAL ;
    ANTENNADIFFAREA 0.340600 ;
    PORT
      LAYER met3 ;
        RECT 969.850 462.440 973.850 463.040 ;
    END
  END debug_redirect_pc_o[19]
  PIN debug_redirect_pc_o[1]
    DIRECTION OUTPUT ;
    USE SIGNAL ;
    ANTENNADIFFAREA 0.340600 ;
    PORT
      LAYER met3 ;
        RECT 0.000 693.640 4.000 694.240 ;
    END
  END debug_redirect_pc_o[1]
  PIN debug_redirect_pc_o[20]
    DIRECTION OUTPUT ;
    USE SIGNAL ;
    ANTENNADIFFAREA 0.340600 ;
    PORT
      LAYER met3 ;
        RECT 0.000 513.440 4.000 514.040 ;
    END
  END debug_redirect_pc_o[20]
  PIN debug_redirect_pc_o[21]
    DIRECTION OUTPUT ;
    USE SIGNAL ;
    ANTENNADIFFAREA 0.340600 ;
    PORT
      LAYER met3 ;
        RECT 0.000 561.040 4.000 561.640 ;
    END
  END debug_redirect_pc_o[21]
  PIN debug_redirect_pc_o[22]
    DIRECTION OUTPUT ;
    USE SIGNAL ;
    ANTENNADIFFAREA 0.340600 ;
    PORT
      LAYER met3 ;
        RECT 0.000 571.240 4.000 571.840 ;
    END
  END debug_redirect_pc_o[22]
  PIN debug_redirect_pc_o[23]
    DIRECTION OUTPUT ;
    USE SIGNAL ;
    ANTENNADIFFAREA 0.340600 ;
    PORT
      LAYER met2 ;
        RECT 405.810 0.000 406.090 4.000 ;
    END
  END debug_redirect_pc_o[23]
  PIN debug_redirect_pc_o[24]
    DIRECTION OUTPUT ;
    USE SIGNAL ;
    ANTENNADIFFAREA 0.340600 ;
    PORT
      LAYER met3 ;
        RECT 0.000 510.040 4.000 510.640 ;
    END
  END debug_redirect_pc_o[24]
  PIN debug_redirect_pc_o[25]
    DIRECTION OUTPUT ;
    USE SIGNAL ;
    ANTENNADIFFAREA 0.340600 ;
    PORT
      LAYER met3 ;
        RECT 0.000 584.840 4.000 585.440 ;
    END
  END debug_redirect_pc_o[25]
  PIN debug_redirect_pc_o[26]
    DIRECTION OUTPUT ;
    USE SIGNAL ;
    ANTENNADIFFAREA 0.340600 ;
    PORT
      LAYER met2 ;
        RECT 415.470 0.000 415.750 4.000 ;
    END
  END debug_redirect_pc_o[26]
  PIN debug_redirect_pc_o[27]
    DIRECTION OUTPUT ;
    USE SIGNAL ;
    ANTENNADIFFAREA 0.340600 ;
    PORT
      LAYER met3 ;
        RECT 0.000 544.040 4.000 544.640 ;
    END
  END debug_redirect_pc_o[27]
  PIN debug_redirect_pc_o[28]
    DIRECTION OUTPUT ;
    USE SIGNAL ;
    ANTENNADIFFAREA 0.340600 ;
    PORT
      LAYER met3 ;
        RECT 0.000 540.640 4.000 541.240 ;
    END
  END debug_redirect_pc_o[28]
  PIN debug_redirect_pc_o[29]
    DIRECTION OUTPUT ;
    USE SIGNAL ;
    ANTENNADIFFAREA 0.340600 ;
    PORT
      LAYER met2 ;
        RECT 418.690 0.000 418.970 4.000 ;
    END
  END debug_redirect_pc_o[29]
  PIN debug_redirect_pc_o[2]
    DIRECTION OUTPUT ;
    USE SIGNAL ;
    ANTENNADIFFAREA 0.340600 ;
    PORT
      LAYER met3 ;
        RECT 0.000 503.240 4.000 503.840 ;
    END
  END debug_redirect_pc_o[2]
  PIN debug_redirect_pc_o[30]
    DIRECTION OUTPUT ;
    USE SIGNAL ;
    ANTENNADIFFAREA 0.340600 ;
    PORT
      LAYER met3 ;
        RECT 0.000 605.240 4.000 605.840 ;
    END
  END debug_redirect_pc_o[30]
  PIN debug_redirect_pc_o[31]
    DIRECTION OUTPUT ;
    USE SIGNAL ;
    ANTENNADIFFAREA 0.340600 ;
    PORT
      LAYER met2 ;
        RECT 447.670 0.000 447.950 4.000 ;
    END
  END debug_redirect_pc_o[31]
  PIN debug_redirect_pc_o[3]
    DIRECTION OUTPUT ;
    USE SIGNAL ;
    ANTENNADIFFAREA 0.340600 ;
    PORT
      LAYER met3 ;
        RECT 0.000 574.640 4.000 575.240 ;
    END
  END debug_redirect_pc_o[3]
  PIN debug_redirect_pc_o[4]
    DIRECTION OUTPUT ;
    USE SIGNAL ;
    ANTENNADIFFAREA 0.340600 ;
    PORT
      LAYER met3 ;
        RECT 0.000 629.040 4.000 629.640 ;
    END
  END debug_redirect_pc_o[4]
  PIN debug_redirect_pc_o[5]
    DIRECTION OUTPUT ;
    USE SIGNAL ;
    ANTENNADIFFAREA 0.340600 ;
    PORT
      LAYER met3 ;
        RECT 0.000 564.440 4.000 565.040 ;
    END
  END debug_redirect_pc_o[5]
  PIN debug_redirect_pc_o[6]
    DIRECTION OUTPUT ;
    USE SIGNAL ;
    ANTENNADIFFAREA 0.340600 ;
    PORT
      LAYER met3 ;
        RECT 0.000 625.640 4.000 626.240 ;
    END
  END debug_redirect_pc_o[6]
  PIN debug_redirect_pc_o[7]
    DIRECTION OUTPUT ;
    USE SIGNAL ;
    ANTENNADIFFAREA 0.340600 ;
    PORT
      LAYER met3 ;
        RECT 0.000 581.440 4.000 582.040 ;
    END
  END debug_redirect_pc_o[7]
  PIN debug_redirect_pc_o[8]
    DIRECTION OUTPUT ;
    USE SIGNAL ;
    ANTENNADIFFAREA 0.340600 ;
    PORT
      LAYER met3 ;
        RECT 969.850 428.440 973.850 429.040 ;
    END
  END debug_redirect_pc_o[8]
  PIN debug_redirect_pc_o[9]
    DIRECTION OUTPUT ;
    USE SIGNAL ;
    ANTENNADIFFAREA 0.340600 ;
    PORT
      LAYER met2 ;
        RECT 421.910 0.000 422.190 4.000 ;
    END
  END debug_redirect_pc_o[9]
  PIN debug_redirect_valid_o
    DIRECTION OUTPUT ;
    USE SIGNAL ;
    ANTENNADIFFAREA 0.340600 ;
    PORT
      LAYER met3 ;
        RECT 0.000 748.040 4.000 748.640 ;
    END
  END debug_redirect_valid_o
  PIN dmem_req_o[0]
    DIRECTION OUTPUT ;
    USE SIGNAL ;
    ANTENNADIFFAREA 0.340600 ;
    PORT
      LAYER met2 ;
        RECT 666.630 980.570 666.910 984.570 ;
    END
  END dmem_req_o[0]
  PIN dmem_req_o[10]
    DIRECTION OUTPUT ;
    USE SIGNAL ;
    ANTENNADIFFAREA 0.340600 ;
    PORT
      LAYER met3 ;
        RECT 969.850 710.640 973.850 711.240 ;
    END
  END dmem_req_o[10]
  PIN dmem_req_o[11]
    DIRECTION OUTPUT ;
    USE SIGNAL ;
    ANTENNADIFFAREA 0.340600 ;
    PORT
      LAYER met3 ;
        RECT 969.850 703.840 973.850 704.440 ;
    END
  END dmem_req_o[11]
  PIN dmem_req_o[12]
    DIRECTION OUTPUT ;
    USE SIGNAL ;
    ANTENNADIFFAREA 0.340600 ;
    PORT
      LAYER met3 ;
        RECT 969.850 734.440 973.850 735.040 ;
    END
  END dmem_req_o[12]
  PIN dmem_req_o[13]
    DIRECTION OUTPUT ;
    USE SIGNAL ;
    ANTENNADIFFAREA 0.340600 ;
    PORT
      LAYER met2 ;
        RECT 782.550 980.570 782.830 984.570 ;
    END
  END dmem_req_o[13]
  PIN dmem_req_o[14]
    DIRECTION OUTPUT ;
    USE SIGNAL ;
    ANTENNADIFFAREA 0.340600 ;
    PORT
      LAYER met3 ;
        RECT 969.850 737.840 973.850 738.440 ;
    END
  END dmem_req_o[14]
  PIN dmem_req_o[15]
    DIRECTION OUTPUT ;
    USE SIGNAL ;
    ANTENNADIFFAREA 0.340600 ;
    PORT
      LAYER met3 ;
        RECT 969.850 731.040 973.850 731.640 ;
    END
  END dmem_req_o[15]
  PIN dmem_req_o[16]
    DIRECTION OUTPUT ;
    USE SIGNAL ;
    ANTENNADIFFAREA 0.340600 ;
    PORT
      LAYER met3 ;
        RECT 969.850 761.640 973.850 762.240 ;
    END
  END dmem_req_o[16]
  PIN dmem_req_o[17]
    DIRECTION OUTPUT ;
    USE SIGNAL ;
    ANTENNADIFFAREA 0.340600 ;
    PORT
      LAYER met3 ;
        RECT 969.850 707.240 973.850 707.840 ;
    END
  END dmem_req_o[17]
  PIN dmem_req_o[18]
    DIRECTION OUTPUT ;
    USE SIGNAL ;
    ANTENNADIFFAREA 0.340600 ;
    PORT
      LAYER met3 ;
        RECT 969.850 680.040 973.850 680.640 ;
    END
  END dmem_req_o[18]
  PIN dmem_req_o[19]
    DIRECTION OUTPUT ;
    USE SIGNAL ;
    ANTENNADIFFAREA 0.340600 ;
    PORT
      LAYER met3 ;
        RECT 969.850 686.840 973.850 687.440 ;
    END
  END dmem_req_o[19]
  PIN dmem_req_o[1]
    DIRECTION OUTPUT ;
    USE SIGNAL ;
    ANTENNADIFFAREA 0.340600 ;
    PORT
      LAYER met2 ;
        RECT 734.250 980.570 734.530 984.570 ;
    END
  END dmem_req_o[1]
  PIN dmem_req_o[20]
    DIRECTION OUTPUT ;
    USE SIGNAL ;
    ANTENNADIFFAREA 0.340600 ;
    PORT
      LAYER met2 ;
        RECT 769.670 980.570 769.950 984.570 ;
    END
  END dmem_req_o[20]
  PIN dmem_req_o[21]
    DIRECTION OUTPUT ;
    USE SIGNAL ;
    ANTENNADIFFAREA 0.340600 ;
    PORT
      LAYER met2 ;
        RECT 731.030 980.570 731.310 984.570 ;
    END
  END dmem_req_o[21]
  PIN dmem_req_o[22]
    DIRECTION OUTPUT ;
    USE SIGNAL ;
    ANTENNADIFFAREA 0.340600 ;
    PORT
      LAYER met2 ;
        RECT 772.890 980.570 773.170 984.570 ;
    END
  END dmem_req_o[22]
  PIN dmem_req_o[23]
    DIRECTION OUTPUT ;
    USE SIGNAL ;
    ANTENNADIFFAREA 0.340600 ;
    PORT
      LAYER met3 ;
        RECT 969.850 751.440 973.850 752.040 ;
    END
  END dmem_req_o[23]
  PIN dmem_req_o[24]
    DIRECTION OUTPUT ;
    USE SIGNAL ;
    ANTENNADIFFAREA 0.340600 ;
    PORT
      LAYER met3 ;
        RECT 969.850 765.040 973.850 765.640 ;
    END
  END dmem_req_o[24]
  PIN dmem_req_o[25]
    DIRECTION OUTPUT ;
    USE SIGNAL ;
    ANTENNADIFFAREA 0.340600 ;
    PORT
      LAYER met3 ;
        RECT 969.850 748.040 973.850 748.640 ;
    END
  END dmem_req_o[25]
  PIN dmem_req_o[26]
    DIRECTION OUTPUT ;
    USE SIGNAL ;
    ANTENNADIFFAREA 0.340600 ;
    PORT
      LAYER met3 ;
        RECT 969.850 724.240 973.850 724.840 ;
    END
  END dmem_req_o[26]
  PIN dmem_req_o[27]
    DIRECTION OUTPUT ;
    USE SIGNAL ;
    ANTENNADIFFAREA 0.340600 ;
    PORT
      LAYER met3 ;
        RECT 969.850 812.640 973.850 813.240 ;
    END
  END dmem_req_o[27]
  PIN dmem_req_o[28]
    DIRECTION OUTPUT ;
    USE SIGNAL ;
    ANTENNADIFFAREA 0.340600 ;
    PORT
      LAYER met3 ;
        RECT 969.850 714.040 973.850 714.640 ;
    END
  END dmem_req_o[28]
  PIN dmem_req_o[29]
    DIRECTION OUTPUT ;
    USE SIGNAL ;
    ANTENNADIFFAREA 0.340600 ;
    PORT
      LAYER met2 ;
        RECT 766.450 980.570 766.730 984.570 ;
    END
  END dmem_req_o[29]
  PIN dmem_req_o[2]
    DIRECTION OUTPUT ;
    USE SIGNAL ;
    ANTENNADIFFAREA 0.340600 ;
    PORT
      LAYER met2 ;
        RECT 753.570 980.570 753.850 984.570 ;
    END
  END dmem_req_o[2]
  PIN dmem_req_o[30]
    DIRECTION OUTPUT ;
    USE SIGNAL ;
    ANTENNADIFFAREA 0.340600 ;
    PORT
      LAYER met2 ;
        RECT 740.690 980.570 740.970 984.570 ;
    END
  END dmem_req_o[30]
  PIN dmem_req_o[31]
    DIRECTION OUTPUT ;
    USE SIGNAL ;
    ANTENNADIFFAREA 0.340600 ;
    PORT
      LAYER met2 ;
        RECT 747.130 980.570 747.410 984.570 ;
    END
  END dmem_req_o[31]
  PIN dmem_req_o[32]
    DIRECTION OUTPUT ;
    USE SIGNAL ;
    ANTENNADIFFAREA 0.340600 ;
    PORT
      LAYER met3 ;
        RECT 969.850 768.440 973.850 769.040 ;
    END
  END dmem_req_o[32]
  PIN dmem_req_o[33]
    DIRECTION OUTPUT ;
    USE SIGNAL ;
    ANTENNADIFFAREA 0.340600 ;
    PORT
      LAYER met3 ;
        RECT 969.850 805.840 973.850 806.440 ;
    END
  END dmem_req_o[33]
  PIN dmem_req_o[34]
    DIRECTION OUTPUT ;
    USE SIGNAL ;
    ANTENNADIFFAREA 0.340600 ;
    PORT
      LAYER met3 ;
        RECT 969.850 720.840 973.850 721.440 ;
    END
  END dmem_req_o[34]
  PIN dmem_req_o[35]
    DIRECTION OUTPUT ;
    USE SIGNAL ;
    ANTENNADIFFAREA 0.340600 ;
    PORT
      LAYER met3 ;
        RECT 969.850 717.440 973.850 718.040 ;
    END
  END dmem_req_o[35]
  PIN dmem_req_o[36]
    DIRECTION OUTPUT ;
    USE SIGNAL ;
    ANTENNADIFFAREA 0.340600 ;
    PORT
      LAYER met2 ;
        RECT 756.790 980.570 757.070 984.570 ;
    END
  END dmem_req_o[36]
  PIN dmem_req_o[37]
    DIRECTION OUTPUT ;
    USE SIGNAL ;
    ANTENNADIFFAREA 0.340600 ;
    PORT
      LAYER met2 ;
        RECT 750.350 980.570 750.630 984.570 ;
    END
  END dmem_req_o[37]
  PIN dmem_req_o[38]
    DIRECTION OUTPUT ;
    USE SIGNAL ;
    ANTENNADIFFAREA 0.340600 ;
    PORT
      LAYER met2 ;
        RECT 760.010 980.570 760.290 984.570 ;
    END
  END dmem_req_o[38]
  PIN dmem_req_o[39]
    DIRECTION OUTPUT ;
    USE SIGNAL ;
    ANTENNADIFFAREA 0.340600 ;
    PORT
      LAYER met3 ;
        RECT 969.850 771.840 973.850 772.440 ;
    END
  END dmem_req_o[39]
  PIN dmem_req_o[3]
    DIRECTION OUTPUT ;
    USE SIGNAL ;
    ANTENNADIFFAREA 0.340600 ;
    PORT
      LAYER met3 ;
        RECT 969.850 700.440 973.850 701.040 ;
    END
  END dmem_req_o[3]
  PIN dmem_req_o[40]
    DIRECTION OUTPUT ;
    USE SIGNAL ;
    ANTENNADIFFAREA 0.340600 ;
    PORT
      LAYER met2 ;
        RECT 727.810 980.570 728.090 984.570 ;
    END
  END dmem_req_o[40]
  PIN dmem_req_o[41]
    DIRECTION OUTPUT ;
    USE SIGNAL ;
    ANTENNADIFFAREA 0.340600 ;
    PORT
      LAYER met2 ;
        RECT 718.150 980.570 718.430 984.570 ;
    END
  END dmem_req_o[41]
  PIN dmem_req_o[42]
    DIRECTION OUTPUT ;
    USE SIGNAL ;
    ANTENNADIFFAREA 0.340600 ;
    PORT
      LAYER met2 ;
        RECT 550.710 980.570 550.990 984.570 ;
    END
  END dmem_req_o[42]
  PIN dmem_req_o[43]
    DIRECTION OUTPUT ;
    USE SIGNAL ;
    ANTENNADIFFAREA 0.340600 ;
    PORT
      LAYER met2 ;
        RECT 360.730 980.570 361.010 984.570 ;
    END
  END dmem_req_o[43]
  PIN dmem_req_o[44]
    DIRECTION OUTPUT ;
    USE SIGNAL ;
    ANTENNADIFFAREA 0.340600 ;
    PORT
      LAYER met2 ;
        RECT 557.150 980.570 557.430 984.570 ;
    END
  END dmem_req_o[44]
  PIN dmem_req_o[45]
    DIRECTION OUTPUT ;
    USE SIGNAL ;
    ANTENNADIFFAREA 0.340600 ;
    PORT
      LAYER met2 ;
        RECT 624.770 980.570 625.050 984.570 ;
    END
  END dmem_req_o[45]
  PIN dmem_req_o[46]
    DIRECTION OUTPUT ;
    USE SIGNAL ;
    ANTENNADIFFAREA 0.340600 ;
    PORT
      LAYER met2 ;
        RECT 640.870 980.570 641.150 984.570 ;
    END
  END dmem_req_o[46]
  PIN dmem_req_o[47]
    DIRECTION OUTPUT ;
    USE SIGNAL ;
    ANTENNADIFFAREA 0.340600 ;
    PORT
      LAYER met2 ;
        RECT 685.950 980.570 686.230 984.570 ;
    END
  END dmem_req_o[47]
  PIN dmem_req_o[48]
    DIRECTION OUTPUT ;
    USE SIGNAL ;
    ANTENNADIFFAREA 0.340600 ;
    PORT
      LAYER met2 ;
        RECT 724.590 980.570 724.870 984.570 ;
    END
  END dmem_req_o[48]
  PIN dmem_req_o[49]
    DIRECTION OUTPUT ;
    USE SIGNAL ;
    ANTENNADIFFAREA 0.340600 ;
    PORT
      LAYER met3 ;
        RECT 969.850 476.040 973.850 476.640 ;
    END
  END dmem_req_o[49]
  PIN dmem_req_o[4]
    DIRECTION OUTPUT ;
    USE SIGNAL ;
    ANTENNADIFFAREA 0.340600 ;
    PORT
      LAYER met3 ;
        RECT 969.850 690.240 973.850 690.840 ;
    END
  END dmem_req_o[4]
  PIN dmem_req_o[50]
    DIRECTION OUTPUT ;
    USE SIGNAL ;
    ANTENNADIFFAREA 0.340600 ;
    PORT
      LAYER met2 ;
        RECT 692.390 980.570 692.670 984.570 ;
    END
  END dmem_req_o[50]
  PIN dmem_req_o[51]
    DIRECTION OUTPUT ;
    USE SIGNAL ;
    ANTENNADIFFAREA 0.340600 ;
    PORT
      LAYER met3 ;
        RECT 969.850 482.840 973.850 483.440 ;
    END
  END dmem_req_o[51]
  PIN dmem_req_o[52]
    DIRECTION OUTPUT ;
    USE SIGNAL ;
    ANTENNADIFFAREA 0.340600 ;
    PORT
      LAYER met2 ;
        RECT 682.730 980.570 683.010 984.570 ;
    END
  END dmem_req_o[52]
  PIN dmem_req_o[53]
    DIRECTION OUTPUT ;
    USE SIGNAL ;
    ANTENNADIFFAREA 0.340600 ;
    PORT
      LAYER met2 ;
        RECT 589.350 980.570 589.630 984.570 ;
    END
  END dmem_req_o[53]
  PIN dmem_req_o[54]
    DIRECTION OUTPUT ;
    USE SIGNAL ;
    ANTENNADIFFAREA 0.340600 ;
    PORT
      LAYER met2 ;
        RECT 673.070 980.570 673.350 984.570 ;
    END
  END dmem_req_o[54]
  PIN dmem_req_o[55]
    DIRECTION OUTPUT ;
    USE SIGNAL ;
    ANTENNADIFFAREA 0.340600 ;
    PORT
      LAYER met3 ;
        RECT 969.850 493.040 973.850 493.640 ;
    END
  END dmem_req_o[55]
  PIN dmem_req_o[56]
    DIRECTION OUTPUT ;
    USE SIGNAL ;
    ANTENNADIFFAREA 0.340600 ;
    PORT
      LAYER met3 ;
        RECT 969.850 499.840 973.850 500.440 ;
    END
  END dmem_req_o[56]
  PIN dmem_req_o[57]
    DIRECTION OUTPUT ;
    USE SIGNAL ;
    ANTENNADIFFAREA 0.340600 ;
    PORT
      LAYER met2 ;
        RECT 676.290 980.570 676.570 984.570 ;
    END
  END dmem_req_o[57]
  PIN dmem_req_o[58]
    DIRECTION OUTPUT ;
    USE SIGNAL ;
    ANTENNADIFFAREA 0.340600 ;
    PORT
      LAYER met2 ;
        RECT 647.310 980.570 647.590 984.570 ;
    END
  END dmem_req_o[58]
  PIN dmem_req_o[59]
    DIRECTION OUTPUT ;
    USE SIGNAL ;
    ANTENNADIFFAREA 0.340600 ;
    PORT
      LAYER met2 ;
        RECT 679.510 980.570 679.790 984.570 ;
    END
  END dmem_req_o[59]
  PIN dmem_req_o[5]
    DIRECTION OUTPUT ;
    USE SIGNAL ;
    ANTENNADIFFAREA 0.340600 ;
    PORT
      LAYER met2 ;
        RECT 763.230 980.570 763.510 984.570 ;
    END
  END dmem_req_o[5]
  PIN dmem_req_o[60]
    DIRECTION OUTPUT ;
    USE SIGNAL ;
    ANTENNADIFFAREA 0.340600 ;
    PORT
      LAYER met2 ;
        RECT 576.470 980.570 576.750 984.570 ;
    END
  END dmem_req_o[60]
  PIN dmem_req_o[61]
    DIRECTION OUTPUT ;
    USE SIGNAL ;
    ANTENNADIFFAREA 0.340600 ;
    PORT
      LAYER met2 ;
        RECT 644.090 980.570 644.370 984.570 ;
    END
  END dmem_req_o[61]
  PIN dmem_req_o[62]
    DIRECTION OUTPUT ;
    USE SIGNAL ;
    ANTENNADIFFAREA 0.340600 ;
    PORT
      LAYER met2 ;
        RECT 595.790 980.570 596.070 984.570 ;
    END
  END dmem_req_o[62]
  PIN dmem_req_o[63]
    DIRECTION OUTPUT ;
    USE SIGNAL ;
    ANTENNADIFFAREA 0.340600 ;
    PORT
      LAYER met2 ;
        RECT 586.130 980.570 586.410 984.570 ;
    END
  END dmem_req_o[63]
  PIN dmem_req_o[64]
    DIRECTION OUTPUT ;
    USE SIGNAL ;
    ANTENNADIFFAREA 0.340600 ;
    PORT
      LAYER met2 ;
        RECT 608.670 980.570 608.950 984.570 ;
    END
  END dmem_req_o[64]
  PIN dmem_req_o[65]
    DIRECTION OUTPUT ;
    USE SIGNAL ;
    ANTENNADIFFAREA 0.340600 ;
    PORT
      LAYER met2 ;
        RECT 534.610 980.570 534.890 984.570 ;
    END
  END dmem_req_o[65]
  PIN dmem_req_o[66]
    DIRECTION OUTPUT ;
    USE SIGNAL ;
    ANTENNADIFFAREA 0.340600 ;
    PORT
      LAYER met2 ;
        RECT 537.830 980.570 538.110 984.570 ;
    END
  END dmem_req_o[66]
  PIN dmem_req_o[67]
    DIRECTION OUTPUT ;
    USE SIGNAL ;
    ANTENNADIFFAREA 0.340600 ;
    PORT
      LAYER met2 ;
        RECT 544.270 980.570 544.550 984.570 ;
    END
  END dmem_req_o[67]
  PIN dmem_req_o[68]
    DIRECTION OUTPUT ;
    USE SIGNAL ;
    ANTENNADIFFAREA 0.340600 ;
    PORT
      LAYER met2 ;
        RECT 357.510 980.570 357.790 984.570 ;
    END
  END dmem_req_o[68]
  PIN dmem_req_o[69]
    DIRECTION OUTPUT ;
    USE SIGNAL ;
    ANTENNADIFFAREA 0.340600 ;
    PORT
      LAYER met2 ;
        RECT 637.650 980.570 637.930 984.570 ;
    END
  END dmem_req_o[69]
  PIN dmem_req_o[6]
    DIRECTION OUTPUT ;
    USE SIGNAL ;
    ANTENNADIFFAREA 0.340600 ;
    PORT
      LAYER met2 ;
        RECT 743.910 980.570 744.190 984.570 ;
    END
  END dmem_req_o[6]
  PIN dmem_req_o[70]
    DIRECTION OUTPUT ;
    USE SIGNAL ;
    ANTENNADIFFAREA 0.340600 ;
    PORT
      LAYER met2 ;
        RECT 463.770 980.570 464.050 984.570 ;
    END
  END dmem_req_o[70]
  PIN dmem_req_o[71]
    DIRECTION OUTPUT ;
    USE SIGNAL ;
    ANTENNADIFFAREA 0.340600 ;
    PORT
      LAYER met2 ;
        RECT 634.430 980.570 634.710 984.570 ;
    END
  END dmem_req_o[71]
  PIN dmem_req_o[7]
    DIRECTION OUTPUT ;
    USE SIGNAL ;
    ANTENNADIFFAREA 0.340600 ;
    PORT
      LAYER met2 ;
        RECT 737.470 980.570 737.750 984.570 ;
    END
  END dmem_req_o[7]
  PIN dmem_req_o[8]
    DIRECTION OUTPUT ;
    USE SIGNAL ;
    ANTENNADIFFAREA 0.340600 ;
    PORT
      LAYER met3 ;
        RECT 969.850 785.440 973.850 786.040 ;
    END
  END dmem_req_o[8]
  PIN dmem_req_o[9]
    DIRECTION OUTPUT ;
    USE SIGNAL ;
    ANTENNADIFFAREA 0.340600 ;
    PORT
      LAYER met3 ;
        RECT 969.850 697.040 973.850 697.640 ;
    END
  END dmem_req_o[9]
  PIN dmem_req_ready_i
    DIRECTION INPUT ;
    USE SIGNAL ;
    ANTENNAGATEAREA 0.213000 ;
    PORT
      LAYER met2 ;
        RECT 660.190 980.570 660.470 984.570 ;
    END
  END dmem_req_ready_i
  PIN dmem_req_valid_o
    DIRECTION OUTPUT ;
    USE SIGNAL ;
    ANTENNADIFFAREA 0.340600 ;
    PORT
      LAYER met2 ;
        RECT 669.850 980.570 670.130 984.570 ;
    END
  END dmem_req_valid_o
  PIN dmem_rsp_i[0]
    DIRECTION INPUT ;
    USE SIGNAL ;
    ANTENNAGATEAREA 0.159000 ;
    PORT
      LAYER met2 ;
        RECT 653.750 980.570 654.030 984.570 ;
    END
  END dmem_rsp_i[0]
  PIN dmem_rsp_i[10]
    DIRECTION INPUT ;
    USE SIGNAL ;
    ANTENNAGATEAREA 0.159000 ;
    PORT
      LAYER met3 ;
        RECT 969.850 550.840 973.850 551.440 ;
    END
  END dmem_rsp_i[10]
  PIN dmem_rsp_i[11]
    DIRECTION INPUT ;
    USE SIGNAL ;
    ANTENNAGATEAREA 0.159000 ;
    PORT
      LAYER met3 ;
        RECT 969.850 527.040 973.850 527.640 ;
    END
  END dmem_rsp_i[11]
  PIN dmem_rsp_i[12]
    DIRECTION INPUT ;
    USE SIGNAL ;
    ANTENNAGATEAREA 0.159000 ;
    PORT
      LAYER met3 ;
        RECT 969.850 513.440 973.850 514.040 ;
    END
  END dmem_rsp_i[12]
  PIN dmem_rsp_i[13]
    DIRECTION INPUT ;
    USE SIGNAL ;
    ANTENNAGATEAREA 0.213000 ;
    PORT
      LAYER met3 ;
        RECT 969.850 608.640 973.850 609.240 ;
    END
  END dmem_rsp_i[13]
  PIN dmem_rsp_i[14]
    DIRECTION INPUT ;
    USE SIGNAL ;
    ANTENNAGATEAREA 0.159000 ;
    PORT
      LAYER met3 ;
        RECT 969.850 557.640 973.850 558.240 ;
    END
  END dmem_rsp_i[14]
  PIN dmem_rsp_i[15]
    DIRECTION INPUT ;
    USE SIGNAL ;
    ANTENNAGATEAREA 0.159000 ;
    PORT
      LAYER met3 ;
        RECT 969.850 533.840 973.850 534.440 ;
    END
  END dmem_rsp_i[15]
  PIN dmem_rsp_i[16]
    DIRECTION INPUT ;
    USE SIGNAL ;
    ANTENNAGATEAREA 0.213000 ;
    PORT
      LAYER met2 ;
        RECT 689.170 980.570 689.450 984.570 ;
    END
  END dmem_rsp_i[16]
  PIN dmem_rsp_i[17]
    DIRECTION INPUT ;
    USE SIGNAL ;
    ANTENNAGATEAREA 0.159000 ;
    PORT
      LAYER met2 ;
        RECT 702.050 980.570 702.330 984.570 ;
    END
  END dmem_rsp_i[17]
  PIN dmem_rsp_i[18]
    DIRECTION INPUT ;
    USE SIGNAL ;
    ANTENNAGATEAREA 0.213000 ;
    PORT
      LAYER met2 ;
        RECT 708.490 980.570 708.770 984.570 ;
    END
  END dmem_rsp_i[18]
  PIN dmem_rsp_i[19]
    DIRECTION INPUT ;
    USE SIGNAL ;
    ANTENNAGATEAREA 0.213000 ;
    PORT
      LAYER met3 ;
        RECT 969.850 523.640 973.850 524.240 ;
    END
  END dmem_rsp_i[19]
  PIN dmem_rsp_i[1]
    DIRECTION INPUT ;
    USE SIGNAL ;
    ANTENNAGATEAREA 0.159000 ;
    PORT
      LAYER met2 ;
        RECT 705.270 980.570 705.550 984.570 ;
    END
  END dmem_rsp_i[1]
  PIN dmem_rsp_i[20]
    DIRECTION INPUT ;
    USE SIGNAL ;
    ANTENNAGATEAREA 0.159000 ;
    PORT
      LAYER met3 ;
        RECT 969.850 567.840 973.850 568.440 ;
    END
  END dmem_rsp_i[20]
  PIN dmem_rsp_i[21]
    DIRECTION INPUT ;
    USE SIGNAL ;
    ANTENNAGATEAREA 0.159000 ;
    PORT
      LAYER met3 ;
        RECT 969.850 571.240 973.850 571.840 ;
    END
  END dmem_rsp_i[21]
  PIN dmem_rsp_i[22]
    DIRECTION INPUT ;
    USE SIGNAL ;
    ANTENNAGATEAREA 0.159000 ;
    PORT
      LAYER met3 ;
        RECT 969.850 605.240 973.850 605.840 ;
    END
  END dmem_rsp_i[22]
  PIN dmem_rsp_i[23]
    DIRECTION INPUT ;
    USE SIGNAL ;
    ANTENNAGATEAREA 0.159000 ;
    PORT
      LAYER met3 ;
        RECT 969.850 547.440 973.850 548.040 ;
    END
  END dmem_rsp_i[23]
  PIN dmem_rsp_i[24]
    DIRECTION INPUT ;
    USE SIGNAL ;
    ANTENNAGATEAREA 0.213000 ;
    PORT
      LAYER met2 ;
        RECT 698.830 980.570 699.110 984.570 ;
    END
  END dmem_rsp_i[24]
  PIN dmem_rsp_i[25]
    DIRECTION INPUT ;
    USE SIGNAL ;
    ANTENNAGATEAREA 0.213000 ;
    PORT
      LAYER met2 ;
        RECT 779.330 980.570 779.610 984.570 ;
    END
  END dmem_rsp_i[25]
  PIN dmem_rsp_i[26]
    DIRECTION INPUT ;
    USE SIGNAL ;
    ANTENNAGATEAREA 0.159000 ;
    PORT
      LAYER met2 ;
        RECT 711.710 980.570 711.990 984.570 ;
    END
  END dmem_rsp_i[26]
  PIN dmem_rsp_i[27]
    DIRECTION INPUT ;
    USE SIGNAL ;
    ANTENNAGATEAREA 0.159000 ;
    PORT
      LAYER met3 ;
        RECT 969.850 544.040 973.850 544.640 ;
    END
  END dmem_rsp_i[27]
  PIN dmem_rsp_i[28]
    DIRECTION INPUT ;
    USE SIGNAL ;
    ANTENNAGATEAREA 0.159000 ;
    PORT
      LAYER met3 ;
        RECT 969.850 537.240 973.850 537.840 ;
    END
  END dmem_rsp_i[28]
  PIN dmem_rsp_i[29]
    DIRECTION INPUT ;
    USE SIGNAL ;
    ANTENNAGATEAREA 0.213000 ;
    PORT
      LAYER met2 ;
        RECT 714.930 980.570 715.210 984.570 ;
    END
  END dmem_rsp_i[29]
  PIN dmem_rsp_i[2]
    DIRECTION INPUT ;
    USE SIGNAL ;
    ANTENNAGATEAREA 0.159000 ;
    PORT
      LAYER met2 ;
        RECT 721.370 980.570 721.650 984.570 ;
    END
  END dmem_rsp_i[2]
  PIN dmem_rsp_i[30]
    DIRECTION INPUT ;
    USE SIGNAL ;
    ANTENNAGATEAREA 0.159000 ;
    PORT
      LAYER met3 ;
        RECT 969.850 564.440 973.850 565.040 ;
    END
  END dmem_rsp_i[30]
  PIN dmem_rsp_i[31]
    DIRECTION INPUT ;
    USE SIGNAL ;
    ANTENNAGATEAREA 0.159000 ;
    PORT
      LAYER met3 ;
        RECT 969.850 530.440 973.850 531.040 ;
    END
  END dmem_rsp_i[31]
  PIN dmem_rsp_i[32]
    DIRECTION INPUT ;
    USE SIGNAL ;
    ANTENNAGATEAREA 0.213000 ;
    PORT
      LAYER met2 ;
        RECT 776.110 980.570 776.390 984.570 ;
    END
  END dmem_rsp_i[32]
  PIN dmem_rsp_i[3]
    DIRECTION INPUT ;
    USE SIGNAL ;
    ANTENNAGATEAREA 0.159000 ;
    PORT
      LAYER met3 ;
        RECT 969.850 516.840 973.850 517.440 ;
    END
  END dmem_rsp_i[3]
  PIN dmem_rsp_i[4]
    DIRECTION INPUT ;
    USE SIGNAL ;
    ANTENNAGATEAREA 0.159000 ;
    PORT
      LAYER met3 ;
        RECT 969.850 561.040 973.850 561.640 ;
    END
  END dmem_rsp_i[4]
  PIN dmem_rsp_i[5]
    DIRECTION INPUT ;
    USE SIGNAL ;
    ANTENNAGATEAREA 0.213000 ;
    PORT
      LAYER met3 ;
        RECT 969.850 591.640 973.850 592.240 ;
    END
  END dmem_rsp_i[5]
  PIN dmem_rsp_i[6]
    DIRECTION INPUT ;
    USE SIGNAL ;
    ANTENNAGATEAREA 0.213000 ;
    PORT
      LAYER met3 ;
        RECT 969.850 574.640 973.850 575.240 ;
    END
  END dmem_rsp_i[6]
  PIN dmem_rsp_i[7]
    DIRECTION INPUT ;
    USE SIGNAL ;
    ANTENNAGATEAREA 0.159000 ;
    PORT
      LAYER met3 ;
        RECT 969.850 554.240 973.850 554.840 ;
    END
  END dmem_rsp_i[7]
  PIN dmem_rsp_i[8]
    DIRECTION INPUT ;
    USE SIGNAL ;
    ANTENNAGATEAREA 0.159000 ;
    PORT
      LAYER met2 ;
        RECT 695.610 980.570 695.890 984.570 ;
    END
  END dmem_rsp_i[8]
  PIN dmem_rsp_i[9]
    DIRECTION INPUT ;
    USE SIGNAL ;
    ANTENNAGATEAREA 0.159000 ;
    PORT
      LAYER met3 ;
        RECT 969.850 520.240 973.850 520.840 ;
    END
  END dmem_rsp_i[9]
  PIN dmem_rsp_ready_o
    DIRECTION OUTPUT ;
    USE SIGNAL ;
    ANTENNADIFFAREA 0.340600 ;
    PORT
      LAYER met2 ;
        RECT 663.410 980.570 663.690 984.570 ;
    END
  END dmem_rsp_ready_o
  PIN dmem_rsp_valid_i
    DIRECTION INPUT ;
    USE SIGNAL ;
    ANTENNAGATEAREA 0.213000 ;
    PORT
      LAYER met2 ;
        RECT 656.970 980.570 657.250 984.570 ;
    END
  END dmem_rsp_valid_i
  PIN imem_req_o[0]
    DIRECTION OUTPUT ;
    USE SIGNAL ;
    ANTENNADIFFAREA 0.340600 ;
    PORT
      LAYER met2 ;
        RECT 402.590 980.570 402.870 984.570 ;
    END
  END imem_req_o[0]
  PIN imem_req_o[10]
    DIRECTION OUTPUT ;
    USE SIGNAL ;
    ANTENNADIFFAREA 0.340600 ;
    PORT
      LAYER met3 ;
        RECT 969.850 618.840 973.850 619.440 ;
    END
  END imem_req_o[10]
  PIN imem_req_o[11]
    DIRECTION OUTPUT ;
    USE SIGNAL ;
    ANTENNADIFFAREA 0.340600 ;
    PORT
      LAYER met2 ;
        RECT 409.030 980.570 409.310 984.570 ;
    END
  END imem_req_o[11]
  PIN imem_req_o[12]
    DIRECTION OUTPUT ;
    USE SIGNAL ;
    ANTENNADIFFAREA 0.340600 ;
    PORT
      LAYER met2 ;
        RECT 389.710 0.000 389.990 4.000 ;
    END
  END imem_req_o[12]
  PIN imem_req_o[13]
    DIRECTION OUTPUT ;
    USE SIGNAL ;
    ANTENNADIFFAREA 0.340600 ;
    PORT
      LAYER met2 ;
        RECT 373.610 0.000 373.890 4.000 ;
    END
  END imem_req_o[13]
  PIN imem_req_o[14]
    DIRECTION OUTPUT ;
    USE SIGNAL ;
    ANTENNADIFFAREA 0.340600 ;
    PORT
      LAYER met2 ;
        RECT 367.170 0.000 367.450 4.000 ;
    END
  END imem_req_o[14]
  PIN imem_req_o[15]
    DIRECTION OUTPUT ;
    USE SIGNAL ;
    ANTENNADIFFAREA 0.340600 ;
    PORT
      LAYER met2 ;
        RECT 450.890 0.000 451.170 4.000 ;
    END
  END imem_req_o[15]
  PIN imem_req_o[16]
    DIRECTION OUTPUT ;
    USE SIGNAL ;
    ANTENNADIFFAREA 0.340600 ;
    PORT
      LAYER met2 ;
        RECT 370.390 0.000 370.670 4.000 ;
    END
  END imem_req_o[16]
  PIN imem_req_o[17]
    DIRECTION OUTPUT ;
    USE SIGNAL ;
    ANTENNADIFFAREA 0.340600 ;
    PORT
      LAYER met2 ;
        RECT 402.590 0.000 402.870 4.000 ;
    END
  END imem_req_o[17]
  PIN imem_req_o[18]
    DIRECTION OUTPUT ;
    USE SIGNAL ;
    ANTENNADIFFAREA 0.340600 ;
    PORT
      LAYER met2 ;
        RECT 383.270 0.000 383.550 4.000 ;
    END
  END imem_req_o[18]
  PIN imem_req_o[19]
    DIRECTION OUTPUT ;
    USE SIGNAL ;
    ANTENNADIFFAREA 0.340600 ;
    PORT
      LAYER met2 ;
        RECT 386.490 0.000 386.770 4.000 ;
    END
  END imem_req_o[19]
  PIN imem_req_o[1]
    DIRECTION OUTPUT ;
    USE SIGNAL ;
    ANTENNADIFFAREA 0.340600 ;
    PORT
      LAYER met2 ;
        RECT 441.230 980.570 441.510 984.570 ;
    END
  END imem_req_o[1]
  PIN imem_req_o[20]
    DIRECTION OUTPUT ;
    USE SIGNAL ;
    ANTENNADIFFAREA 0.340600 ;
    PORT
      LAYER met2 ;
        RECT 431.570 0.000 431.850 4.000 ;
    END
  END imem_req_o[20]
  PIN imem_req_o[21]
    DIRECTION OUTPUT ;
    USE SIGNAL ;
    ANTENNADIFFAREA 0.340600 ;
    PORT
      LAYER met2 ;
        RECT 412.250 0.000 412.530 4.000 ;
    END
  END imem_req_o[21]
  PIN imem_req_o[22]
    DIRECTION OUTPUT ;
    USE SIGNAL ;
    ANTENNADIFFAREA 0.340600 ;
    PORT
      LAYER met2 ;
        RECT 460.550 0.000 460.830 4.000 ;
    END
  END imem_req_o[22]
  PIN imem_req_o[23]
    DIRECTION OUTPUT ;
    USE SIGNAL ;
    ANTENNADIFFAREA 0.340600 ;
    PORT
      LAYER met2 ;
        RECT 441.230 0.000 441.510 4.000 ;
    END
  END imem_req_o[23]
  PIN imem_req_o[24]
    DIRECTION OUTPUT ;
    USE SIGNAL ;
    ANTENNADIFFAREA 0.340600 ;
    PORT
      LAYER met2 ;
        RECT 360.730 0.000 361.010 4.000 ;
    END
  END imem_req_o[24]
  PIN imem_req_o[25]
    DIRECTION OUTPUT ;
    USE SIGNAL ;
    ANTENNADIFFAREA 0.340600 ;
    PORT
      LAYER met2 ;
        RECT 363.950 0.000 364.230 4.000 ;
    END
  END imem_req_o[25]
  PIN imem_req_o[26]
    DIRECTION OUTPUT ;
    USE SIGNAL ;
    ANTENNADIFFAREA 0.340600 ;
    PORT
      LAYER met2 ;
        RECT 380.050 0.000 380.330 4.000 ;
    END
  END imem_req_o[26]
  PIN imem_req_o[27]
    DIRECTION OUTPUT ;
    USE SIGNAL ;
    ANTENNADIFFAREA 0.340600 ;
    PORT
      LAYER met2 ;
        RECT 434.790 0.000 435.070 4.000 ;
    END
  END imem_req_o[27]
  PIN imem_req_o[28]
    DIRECTION OUTPUT ;
    USE SIGNAL ;
    ANTENNADIFFAREA 0.340600 ;
    PORT
      LAYER met2 ;
        RECT 376.830 0.000 377.110 4.000 ;
    END
  END imem_req_o[28]
  PIN imem_req_o[29]
    DIRECTION OUTPUT ;
    USE SIGNAL ;
    ANTENNADIFFAREA 0.340600 ;
    PORT
      LAYER met3 ;
        RECT 0.000 591.640 4.000 592.240 ;
    END
  END imem_req_o[29]
  PIN imem_req_o[2]
    DIRECTION OUTPUT ;
    USE SIGNAL ;
    ANTENNADIFFAREA 0.340600 ;
    PORT
      LAYER met2 ;
        RECT 421.910 980.570 422.190 984.570 ;
    END
  END imem_req_o[2]
  PIN imem_req_o[30]
    DIRECTION OUTPUT ;
    USE SIGNAL ;
    ANTENNADIFFAREA 0.340600 ;
    PORT
      LAYER met3 ;
        RECT 0.000 588.240 4.000 588.840 ;
    END
  END imem_req_o[30]
  PIN imem_req_o[31]
    DIRECTION OUTPUT ;
    USE SIGNAL ;
    ANTENNADIFFAREA 0.340600 ;
    PORT
      LAYER met3 ;
        RECT 0.000 598.440 4.000 599.040 ;
    END
  END imem_req_o[31]
  PIN imem_req_o[32]
    DIRECTION OUTPUT ;
    USE SIGNAL ;
    ANTENNADIFFAREA 0.340600 ;
    PORT
      LAYER met3 ;
        RECT 0.000 618.840 4.000 619.440 ;
    END
  END imem_req_o[32]
  PIN imem_req_o[33]
    DIRECTION OUTPUT ;
    USE SIGNAL ;
    ANTENNADIFFAREA 0.340600 ;
    PORT
      LAYER met3 ;
        RECT 0.000 649.440 4.000 650.040 ;
    END
  END imem_req_o[33]
  PIN imem_req_o[34]
    DIRECTION OUTPUT ;
    USE SIGNAL ;
    ANTENNADIFFAREA 0.340600 ;
    PORT
      LAYER met3 ;
        RECT 0.000 622.240 4.000 622.840 ;
    END
  END imem_req_o[34]
  PIN imem_req_o[35]
    DIRECTION OUTPUT ;
    USE SIGNAL ;
    ANTENNADIFFAREA 0.340600 ;
    PORT
      LAYER met2 ;
        RECT 392.930 0.000 393.210 4.000 ;
    END
  END imem_req_o[35]
  PIN imem_req_o[3]
    DIRECTION OUTPUT ;
    USE SIGNAL ;
    ANTENNADIFFAREA 0.340600 ;
    PORT
      LAYER met2 ;
        RECT 428.350 980.570 428.630 984.570 ;
    END
  END imem_req_o[3]
  PIN imem_req_o[4]
    DIRECTION OUTPUT ;
    USE SIGNAL ;
    ANTENNADIFFAREA 0.340600 ;
    PORT
      LAYER met3 ;
        RECT 0.000 703.840 4.000 704.440 ;
    END
  END imem_req_o[4]
  PIN imem_req_o[5]
    DIRECTION OUTPUT ;
    USE SIGNAL ;
    ANTENNADIFFAREA 0.340600 ;
    PORT
      LAYER met3 ;
        RECT 0.000 700.440 4.000 701.040 ;
    END
  END imem_req_o[5]
  PIN imem_req_o[6]
    DIRECTION OUTPUT ;
    USE SIGNAL ;
    ANTENNADIFFAREA 0.340600 ;
    PORT
      LAYER met2 ;
        RECT 438.010 0.000 438.290 4.000 ;
    END
  END imem_req_o[6]
  PIN imem_req_o[7]
    DIRECTION OUTPUT ;
    USE SIGNAL ;
    ANTENNADIFFAREA 0.340600 ;
    PORT
      LAYER met3 ;
        RECT 0.000 683.440 4.000 684.040 ;
    END
  END imem_req_o[7]
  PIN imem_req_o[8]
    DIRECTION OUTPUT ;
    USE SIGNAL ;
    ANTENNADIFFAREA 0.340600 ;
    PORT
      LAYER met3 ;
        RECT 0.000 673.240 4.000 673.840 ;
    END
  END imem_req_o[8]
  PIN imem_req_o[9]
    DIRECTION OUTPUT ;
    USE SIGNAL ;
    ANTENNADIFFAREA 0.340600 ;
    PORT
      LAYER met3 ;
        RECT 969.850 503.240 973.850 503.840 ;
    END
  END imem_req_o[9]
  PIN imem_req_ready_i
    DIRECTION INPUT ;
    USE SIGNAL ;
    ANTENNAGATEAREA 0.247500 ;
    PORT
      LAYER met3 ;
        RECT 0.000 707.240 4.000 707.840 ;
    END
  END imem_req_ready_i
  PIN imem_req_valid_o
    DIRECTION OUTPUT ;
    USE SIGNAL ;
    ANTENNADIFFAREA 0.340600 ;
    PORT
      LAYER met2 ;
        RECT 399.370 980.570 399.650 984.570 ;
    END
  END imem_req_valid_o
  PIN imem_rsp_i[0]
    DIRECTION INPUT ;
    USE SIGNAL ;
    ANTENNAGATEAREA 0.213000 ;
    PORT
      LAYER met2 ;
        RECT 438.010 980.570 438.290 984.570 ;
    END
  END imem_rsp_i[0]
  PIN imem_rsp_i[10]
    DIRECTION INPUT ;
    USE SIGNAL ;
    ANTENNAGATEAREA 0.126000 ;
    PORT
      LAYER met2 ;
        RECT 457.330 980.570 457.610 984.570 ;
    END
  END imem_rsp_i[10]
  PIN imem_rsp_i[11]
    DIRECTION INPUT ;
    USE SIGNAL ;
    ANTENNAGATEAREA 0.126000 ;
    PORT
      LAYER met2 ;
        RECT 492.750 980.570 493.030 984.570 ;
    END
  END imem_rsp_i[11]
  PIN imem_rsp_i[12]
    DIRECTION INPUT ;
    USE SIGNAL ;
    ANTENNAGATEAREA 0.126000 ;
    PORT
      LAYER met2 ;
        RECT 579.690 980.570 579.970 984.570 ;
    END
  END imem_rsp_i[12]
  PIN imem_rsp_i[13]
    DIRECTION INPUT ;
    USE SIGNAL ;
    ANTENNAGATEAREA 0.213000 ;
    PORT
      LAYER met3 ;
        RECT 969.850 380.840 973.850 381.440 ;
    END
  END imem_rsp_i[13]
  PIN imem_rsp_i[14]
    DIRECTION INPUT ;
    USE SIGNAL ;
    ANTENNAGATEAREA 0.213000 ;
    PORT
      LAYER met3 ;
        RECT 969.850 353.640 973.850 354.240 ;
    END
  END imem_rsp_i[14]
  PIN imem_rsp_i[15]
    DIRECTION INPUT ;
    USE SIGNAL ;
    ANTENNAGATEAREA 0.159000 ;
    PORT
      LAYER met3 ;
        RECT 969.850 370.640 973.850 371.240 ;
    END
  END imem_rsp_i[15]
  PIN imem_rsp_i[16]
    DIRECTION INPUT ;
    USE SIGNAL ;
    ANTENNAGATEAREA 0.159000 ;
    PORT
      LAYER met3 ;
        RECT 969.850 408.040 973.850 408.640 ;
    END
  END imem_rsp_i[16]
  PIN imem_rsp_i[17]
    DIRECTION INPUT ;
    USE SIGNAL ;
    ANTENNAGATEAREA 0.213000 ;
    PORT
      LAYER met2 ;
        RECT 602.230 980.570 602.510 984.570 ;
    END
  END imem_rsp_i[17]
  PIN imem_rsp_i[18]
    DIRECTION INPUT ;
    USE SIGNAL ;
    ANTENNAGATEAREA 0.196500 ;
    PORT
      LAYER met2 ;
        RECT 570.030 980.570 570.310 984.570 ;
    END
  END imem_rsp_i[18]
  PIN imem_rsp_i[19]
    DIRECTION INPUT ;
    USE SIGNAL ;
    ANTENNAGATEAREA 0.196500 ;
    PORT
      LAYER met2 ;
        RECT 582.910 980.570 583.190 984.570 ;
    END
  END imem_rsp_i[19]
  PIN imem_rsp_i[1]
    DIRECTION INPUT ;
    USE SIGNAL ;
    ANTENNAGATEAREA 0.213000 ;
    PORT
      LAYER met2 ;
        RECT 373.610 980.570 373.890 984.570 ;
    END
  END imem_rsp_i[1]
  PIN imem_rsp_i[20]
    DIRECTION INPUT ;
    USE SIGNAL ;
    ANTENNAGATEAREA 0.196500 ;
    PORT
      LAYER met3 ;
        RECT 969.850 343.440 973.850 344.040 ;
    END
  END imem_rsp_i[20]
  PIN imem_rsp_i[21]
    DIRECTION INPUT ;
    USE SIGNAL ;
    ANTENNAGATEAREA 0.196500 ;
    PORT
      LAYER met3 ;
        RECT 969.850 312.840 973.850 313.440 ;
    END
  END imem_rsp_i[21]
  PIN imem_rsp_i[22]
    DIRECTION INPUT ;
    USE SIGNAL ;
    ANTENNAGATEAREA 0.196500 ;
    PORT
      LAYER met3 ;
        RECT 969.850 329.840 973.850 330.440 ;
    END
  END imem_rsp_i[22]
  PIN imem_rsp_i[23]
    DIRECTION INPUT ;
    USE SIGNAL ;
    ANTENNAGATEAREA 0.196500 ;
    PORT
      LAYER met3 ;
        RECT 969.850 326.440 973.850 327.040 ;
    END
  END imem_rsp_i[23]
  PIN imem_rsp_i[24]
    DIRECTION INPUT ;
    USE SIGNAL ;
    ANTENNAGATEAREA 0.196500 ;
    PORT
      LAYER met3 ;
        RECT 969.850 292.440 973.850 293.040 ;
    END
  END imem_rsp_i[24]
  PIN imem_rsp_i[25]
    DIRECTION INPUT ;
    USE SIGNAL ;
    ANTENNAGATEAREA 0.196500 ;
    PORT
      LAYER met3 ;
        RECT 969.850 323.040 973.850 323.640 ;
    END
  END imem_rsp_i[25]
  PIN imem_rsp_i[26]
    DIRECTION INPUT ;
    USE SIGNAL ;
    ANTENNAGATEAREA 0.196500 ;
    PORT
      LAYER met3 ;
        RECT 969.850 319.640 973.850 320.240 ;
    END
  END imem_rsp_i[26]
  PIN imem_rsp_i[27]
    DIRECTION INPUT ;
    USE SIGNAL ;
    ANTENNAGATEAREA 0.196500 ;
    PORT
      LAYER met3 ;
        RECT 969.850 333.240 973.850 333.840 ;
    END
  END imem_rsp_i[27]
  PIN imem_rsp_i[28]
    DIRECTION INPUT ;
    USE SIGNAL ;
    ANTENNAGATEAREA 0.196500 ;
    PORT
      LAYER met3 ;
        RECT 969.850 336.640 973.850 337.240 ;
    END
  END imem_rsp_i[28]
  PIN imem_rsp_i[29]
    DIRECTION INPUT ;
    USE SIGNAL ;
    ANTENNAGATEAREA 0.196500 ;
    PORT
      LAYER met3 ;
        RECT 969.850 340.040 973.850 340.640 ;
    END
  END imem_rsp_i[29]
  PIN imem_rsp_i[2]
    DIRECTION INPUT ;
    USE SIGNAL ;
    ANTENNAGATEAREA 0.126000 ;
    PORT
      LAYER met2 ;
        RECT 431.570 980.570 431.850 984.570 ;
    END
  END imem_rsp_i[2]
  PIN imem_rsp_i[30]
    DIRECTION INPUT ;
    USE SIGNAL ;
    ANTENNAGATEAREA 0.213000 ;
    PORT
      LAYER met2 ;
        RECT 563.590 980.570 563.870 984.570 ;
    END
  END imem_rsp_i[30]
  PIN imem_rsp_i[31]
    DIRECTION INPUT ;
    USE SIGNAL ;
    ANTENNAGATEAREA 0.126000 ;
    PORT
      LAYER met2 ;
        RECT 486.310 980.570 486.590 984.570 ;
    END
  END imem_rsp_i[31]
  PIN imem_rsp_i[32]
    DIRECTION INPUT ;
    USE SIGNAL ;
    ANTENNAGATEAREA 0.126000 ;
    PORT
      LAYER met2 ;
        RECT 460.550 980.570 460.830 984.570 ;
    END
  END imem_rsp_i[32]
  PIN imem_rsp_i[33]
    DIRECTION INPUT ;
    USE SIGNAL ;
    ANTENNAGATEAREA 0.213000 ;
    PORT
      LAYER met2 ;
        RECT 512.070 980.570 512.350 984.570 ;
    END
  END imem_rsp_i[33]
  PIN imem_rsp_i[34]
    DIRECTION INPUT ;
    USE SIGNAL ;
    ANTENNAGATEAREA 0.213000 ;
    PORT
      LAYER met2 ;
        RECT 621.550 980.570 621.830 984.570 ;
    END
  END imem_rsp_i[34]
  PIN imem_rsp_i[35]
    DIRECTION INPUT ;
    USE SIGNAL ;
    ANTENNAGATEAREA 0.126000 ;
    PORT
      LAYER met2 ;
        RECT 518.510 980.570 518.790 984.570 ;
    END
  END imem_rsp_i[35]
  PIN imem_rsp_i[36]
    DIRECTION INPUT ;
    USE SIGNAL ;
    ANTENNAGATEAREA 0.213000 ;
    PORT
      LAYER met2 ;
        RECT 528.170 980.570 528.450 984.570 ;
    END
  END imem_rsp_i[36]
  PIN imem_rsp_i[3]
    DIRECTION INPUT ;
    USE SIGNAL ;
    ANTENNAGATEAREA 0.213000 ;
    PORT
      LAYER met2 ;
        RECT 370.390 980.570 370.670 984.570 ;
    END
  END imem_rsp_i[3]
  PIN imem_rsp_i[4]
    DIRECTION INPUT ;
    USE SIGNAL ;
    ANTENNAGATEAREA 0.196500 ;
    PORT
      LAYER met2 ;
        RECT 495.970 980.570 496.250 984.570 ;
    END
  END imem_rsp_i[4]
  PIN imem_rsp_i[5]
    DIRECTION INPUT ;
    USE SIGNAL ;
    ANTENNAGATEAREA 0.213000 ;
    PORT
      LAYER met2 ;
        RECT 605.450 980.570 605.730 984.570 ;
    END
  END imem_rsp_i[5]
  PIN imem_rsp_i[6]
    DIRECTION INPUT ;
    USE SIGNAL ;
    ANTENNAGATEAREA 0.213000 ;
    PORT
      LAYER met2 ;
        RECT 573.250 980.570 573.530 984.570 ;
    END
  END imem_rsp_i[6]
  PIN imem_rsp_i[7]
    DIRECTION INPUT ;
    USE SIGNAL ;
    ANTENNAGATEAREA 0.213000 ;
    PORT
      LAYER met2 ;
        RECT 631.210 980.570 631.490 984.570 ;
    END
  END imem_rsp_i[7]
  PIN imem_rsp_i[8]
    DIRECTION INPUT ;
    USE SIGNAL ;
    ANTENNAGATEAREA 0.213000 ;
    PORT
      LAYER met2 ;
        RECT 396.150 980.570 396.430 984.570 ;
    END
  END imem_rsp_i[8]
  PIN imem_rsp_i[9]
    DIRECTION INPUT ;
    USE SIGNAL ;
    ANTENNAGATEAREA 0.213000 ;
    PORT
      LAYER met2 ;
        RECT 450.890 980.570 451.170 984.570 ;
    END
  END imem_rsp_i[9]
  PIN imem_rsp_ready_o
    DIRECTION OUTPUT ;
    USE SIGNAL ;
    ANTENNADIFFAREA 0.340600 ;
    PORT
      LAYER met2 ;
        RECT 415.470 980.570 415.750 984.570 ;
    END
  END imem_rsp_ready_o
  PIN imem_rsp_valid_i
    DIRECTION INPUT ;
    USE SIGNAL ;
    ANTENNAGATEAREA 0.213000 ;
    PORT
      LAYER met2 ;
        RECT 412.250 980.570 412.530 984.570 ;
    END
  END imem_rsp_valid_i
  PIN rst_ni
    DIRECTION INPUT ;
    USE SIGNAL ;
    ANTENNAGATEAREA 0.852000 ;
    PORT
      LAYER met3 ;
        RECT 0.000 911.240 4.000 911.840 ;
    END
  END rst_ni
  OBS
      LAYER nwell ;
        RECT 5.330 10.795 968.490 971.230 ;
      LAYER li1 ;
        RECT 5.520 10.795 968.300 971.125 ;
      LAYER met1 ;
        RECT 4.210 10.640 968.300 971.280 ;
      LAYER met2 ;
        RECT 4.230 980.290 354.010 980.570 ;
        RECT 354.850 980.290 357.230 980.570 ;
        RECT 358.070 980.290 360.450 980.570 ;
        RECT 361.290 980.290 363.670 980.570 ;
        RECT 364.510 980.290 366.890 980.570 ;
        RECT 367.730 980.290 370.110 980.570 ;
        RECT 370.950 980.290 373.330 980.570 ;
        RECT 374.170 980.290 376.550 980.570 ;
        RECT 377.390 980.290 379.770 980.570 ;
        RECT 380.610 980.290 382.990 980.570 ;
        RECT 383.830 980.290 386.210 980.570 ;
        RECT 387.050 980.290 389.430 980.570 ;
        RECT 390.270 980.290 392.650 980.570 ;
        RECT 393.490 980.290 395.870 980.570 ;
        RECT 396.710 980.290 399.090 980.570 ;
        RECT 399.930 980.290 402.310 980.570 ;
        RECT 403.150 980.290 405.530 980.570 ;
        RECT 406.370 980.290 408.750 980.570 ;
        RECT 409.590 980.290 411.970 980.570 ;
        RECT 412.810 980.290 415.190 980.570 ;
        RECT 416.030 980.290 418.410 980.570 ;
        RECT 419.250 980.290 421.630 980.570 ;
        RECT 422.470 980.290 424.850 980.570 ;
        RECT 425.690 980.290 428.070 980.570 ;
        RECT 428.910 980.290 431.290 980.570 ;
        RECT 432.130 980.290 434.510 980.570 ;
        RECT 435.350 980.290 437.730 980.570 ;
        RECT 438.570 980.290 440.950 980.570 ;
        RECT 441.790 980.290 444.170 980.570 ;
        RECT 445.010 980.290 447.390 980.570 ;
        RECT 448.230 980.290 450.610 980.570 ;
        RECT 451.450 980.290 453.830 980.570 ;
        RECT 454.670 980.290 457.050 980.570 ;
        RECT 457.890 980.290 460.270 980.570 ;
        RECT 461.110 980.290 463.490 980.570 ;
        RECT 464.330 980.290 466.710 980.570 ;
        RECT 467.550 980.290 469.930 980.570 ;
        RECT 470.770 980.290 473.150 980.570 ;
        RECT 473.990 980.290 476.370 980.570 ;
        RECT 477.210 980.290 479.590 980.570 ;
        RECT 480.430 980.290 482.810 980.570 ;
        RECT 483.650 980.290 486.030 980.570 ;
        RECT 486.870 980.290 489.250 980.570 ;
        RECT 490.090 980.290 492.470 980.570 ;
        RECT 493.310 980.290 495.690 980.570 ;
        RECT 496.530 980.290 498.910 980.570 ;
        RECT 499.750 980.290 502.130 980.570 ;
        RECT 502.970 980.290 505.350 980.570 ;
        RECT 506.190 980.290 508.570 980.570 ;
        RECT 509.410 980.290 511.790 980.570 ;
        RECT 512.630 980.290 515.010 980.570 ;
        RECT 515.850 980.290 518.230 980.570 ;
        RECT 519.070 980.290 521.450 980.570 ;
        RECT 522.290 980.290 524.670 980.570 ;
        RECT 525.510 980.290 527.890 980.570 ;
        RECT 528.730 980.290 531.110 980.570 ;
        RECT 531.950 980.290 534.330 980.570 ;
        RECT 535.170 980.290 537.550 980.570 ;
        RECT 538.390 980.290 540.770 980.570 ;
        RECT 541.610 980.290 543.990 980.570 ;
        RECT 544.830 980.290 547.210 980.570 ;
        RECT 548.050 980.290 550.430 980.570 ;
        RECT 551.270 980.290 553.650 980.570 ;
        RECT 554.490 980.290 556.870 980.570 ;
        RECT 557.710 980.290 560.090 980.570 ;
        RECT 560.930 980.290 563.310 980.570 ;
        RECT 564.150 980.290 566.530 980.570 ;
        RECT 567.370 980.290 569.750 980.570 ;
        RECT 570.590 980.290 572.970 980.570 ;
        RECT 573.810 980.290 576.190 980.570 ;
        RECT 577.030 980.290 579.410 980.570 ;
        RECT 580.250 980.290 582.630 980.570 ;
        RECT 583.470 980.290 585.850 980.570 ;
        RECT 586.690 980.290 589.070 980.570 ;
        RECT 589.910 980.290 592.290 980.570 ;
        RECT 593.130 980.290 595.510 980.570 ;
        RECT 596.350 980.290 598.730 980.570 ;
        RECT 599.570 980.290 601.950 980.570 ;
        RECT 602.790 980.290 605.170 980.570 ;
        RECT 606.010 980.290 608.390 980.570 ;
        RECT 609.230 980.290 611.610 980.570 ;
        RECT 612.450 980.290 614.830 980.570 ;
        RECT 615.670 980.290 618.050 980.570 ;
        RECT 618.890 980.290 621.270 980.570 ;
        RECT 622.110 980.290 624.490 980.570 ;
        RECT 625.330 980.290 627.710 980.570 ;
        RECT 628.550 980.290 630.930 980.570 ;
        RECT 631.770 980.290 634.150 980.570 ;
        RECT 634.990 980.290 637.370 980.570 ;
        RECT 638.210 980.290 640.590 980.570 ;
        RECT 641.430 980.290 643.810 980.570 ;
        RECT 644.650 980.290 647.030 980.570 ;
        RECT 647.870 980.290 650.250 980.570 ;
        RECT 651.090 980.290 653.470 980.570 ;
        RECT 654.310 980.290 656.690 980.570 ;
        RECT 657.530 980.290 659.910 980.570 ;
        RECT 660.750 980.290 663.130 980.570 ;
        RECT 663.970 980.290 666.350 980.570 ;
        RECT 667.190 980.290 669.570 980.570 ;
        RECT 670.410 980.290 672.790 980.570 ;
        RECT 673.630 980.290 676.010 980.570 ;
        RECT 676.850 980.290 679.230 980.570 ;
        RECT 680.070 980.290 682.450 980.570 ;
        RECT 683.290 980.290 685.670 980.570 ;
        RECT 686.510 980.290 688.890 980.570 ;
        RECT 689.730 980.290 692.110 980.570 ;
        RECT 692.950 980.290 695.330 980.570 ;
        RECT 696.170 980.290 698.550 980.570 ;
        RECT 699.390 980.290 701.770 980.570 ;
        RECT 702.610 980.290 704.990 980.570 ;
        RECT 705.830 980.290 708.210 980.570 ;
        RECT 709.050 980.290 711.430 980.570 ;
        RECT 712.270 980.290 714.650 980.570 ;
        RECT 715.490 980.290 717.870 980.570 ;
        RECT 718.710 980.290 721.090 980.570 ;
        RECT 721.930 980.290 724.310 980.570 ;
        RECT 725.150 980.290 727.530 980.570 ;
        RECT 728.370 980.290 730.750 980.570 ;
        RECT 731.590 980.290 733.970 980.570 ;
        RECT 734.810 980.290 737.190 980.570 ;
        RECT 738.030 980.290 740.410 980.570 ;
        RECT 741.250 980.290 743.630 980.570 ;
        RECT 744.470 980.290 746.850 980.570 ;
        RECT 747.690 980.290 750.070 980.570 ;
        RECT 750.910 980.290 753.290 980.570 ;
        RECT 754.130 980.290 756.510 980.570 ;
        RECT 757.350 980.290 759.730 980.570 ;
        RECT 760.570 980.290 762.950 980.570 ;
        RECT 763.790 980.290 766.170 980.570 ;
        RECT 767.010 980.290 769.390 980.570 ;
        RECT 770.230 980.290 772.610 980.570 ;
        RECT 773.450 980.290 775.830 980.570 ;
        RECT 776.670 980.290 779.050 980.570 ;
        RECT 779.890 980.290 782.270 980.570 ;
        RECT 783.110 980.290 967.290 980.570 ;
        RECT 4.230 4.280 967.290 980.290 ;
        RECT 4.230 4.000 360.450 4.280 ;
        RECT 361.290 4.000 363.670 4.280 ;
        RECT 364.510 4.000 366.890 4.280 ;
        RECT 367.730 4.000 370.110 4.280 ;
        RECT 370.950 4.000 373.330 4.280 ;
        RECT 374.170 4.000 376.550 4.280 ;
        RECT 377.390 4.000 379.770 4.280 ;
        RECT 380.610 4.000 382.990 4.280 ;
        RECT 383.830 4.000 386.210 4.280 ;
        RECT 387.050 4.000 389.430 4.280 ;
        RECT 390.270 4.000 392.650 4.280 ;
        RECT 393.490 4.000 395.870 4.280 ;
        RECT 396.710 4.000 399.090 4.280 ;
        RECT 399.930 4.000 402.310 4.280 ;
        RECT 403.150 4.000 405.530 4.280 ;
        RECT 406.370 4.000 408.750 4.280 ;
        RECT 409.590 4.000 411.970 4.280 ;
        RECT 412.810 4.000 415.190 4.280 ;
        RECT 416.030 4.000 418.410 4.280 ;
        RECT 419.250 4.000 421.630 4.280 ;
        RECT 422.470 4.000 424.850 4.280 ;
        RECT 425.690 4.000 428.070 4.280 ;
        RECT 428.910 4.000 431.290 4.280 ;
        RECT 432.130 4.000 434.510 4.280 ;
        RECT 435.350 4.000 437.730 4.280 ;
        RECT 438.570 4.000 440.950 4.280 ;
        RECT 441.790 4.000 444.170 4.280 ;
        RECT 445.010 4.000 447.390 4.280 ;
        RECT 448.230 4.000 450.610 4.280 ;
        RECT 451.450 4.000 453.830 4.280 ;
        RECT 454.670 4.000 457.050 4.280 ;
        RECT 457.890 4.000 460.270 4.280 ;
        RECT 461.110 4.000 967.290 4.280 ;
      LAYER met3 ;
        RECT 3.990 915.640 969.850 971.205 ;
        RECT 4.400 914.240 969.850 915.640 ;
        RECT 3.990 912.240 969.850 914.240 ;
        RECT 4.400 910.840 969.850 912.240 ;
        RECT 3.990 817.040 969.850 910.840 ;
        RECT 3.990 815.640 969.450 817.040 ;
        RECT 3.990 813.640 969.850 815.640 ;
        RECT 3.990 812.240 969.450 813.640 ;
        RECT 3.990 810.240 969.850 812.240 ;
        RECT 3.990 808.840 969.450 810.240 ;
        RECT 3.990 806.840 969.850 808.840 ;
        RECT 3.990 805.440 969.450 806.840 ;
        RECT 3.990 803.440 969.850 805.440 ;
        RECT 3.990 802.040 969.450 803.440 ;
        RECT 3.990 800.040 969.850 802.040 ;
        RECT 3.990 798.640 969.450 800.040 ;
        RECT 3.990 796.640 969.850 798.640 ;
        RECT 3.990 795.240 969.450 796.640 ;
        RECT 3.990 793.240 969.850 795.240 ;
        RECT 3.990 791.840 969.450 793.240 ;
        RECT 3.990 789.840 969.850 791.840 ;
        RECT 3.990 788.440 969.450 789.840 ;
        RECT 3.990 786.440 969.850 788.440 ;
        RECT 3.990 785.040 969.450 786.440 ;
        RECT 3.990 783.040 969.850 785.040 ;
        RECT 3.990 781.640 969.450 783.040 ;
        RECT 3.990 779.640 969.850 781.640 ;
        RECT 3.990 778.240 969.450 779.640 ;
        RECT 3.990 776.240 969.850 778.240 ;
        RECT 3.990 774.840 969.450 776.240 ;
        RECT 3.990 772.840 969.850 774.840 ;
        RECT 3.990 771.440 969.450 772.840 ;
        RECT 3.990 769.440 969.850 771.440 ;
        RECT 3.990 768.040 969.450 769.440 ;
        RECT 3.990 766.040 969.850 768.040 ;
        RECT 3.990 764.640 969.450 766.040 ;
        RECT 3.990 762.640 969.850 764.640 ;
        RECT 3.990 761.240 969.450 762.640 ;
        RECT 3.990 759.240 969.850 761.240 ;
        RECT 3.990 757.840 969.450 759.240 ;
        RECT 3.990 755.840 969.850 757.840 ;
        RECT 3.990 754.440 969.450 755.840 ;
        RECT 3.990 752.440 969.850 754.440 ;
        RECT 3.990 751.040 969.450 752.440 ;
        RECT 3.990 749.040 969.850 751.040 ;
        RECT 4.400 747.640 969.450 749.040 ;
        RECT 3.990 745.640 969.850 747.640 ;
        RECT 3.990 744.240 969.450 745.640 ;
        RECT 3.990 742.240 969.850 744.240 ;
        RECT 3.990 740.840 969.450 742.240 ;
        RECT 3.990 738.840 969.850 740.840 ;
        RECT 3.990 737.440 969.450 738.840 ;
        RECT 3.990 735.440 969.850 737.440 ;
        RECT 3.990 734.040 969.450 735.440 ;
        RECT 3.990 732.040 969.850 734.040 ;
        RECT 3.990 730.640 969.450 732.040 ;
        RECT 3.990 728.640 969.850 730.640 ;
        RECT 3.990 727.240 969.450 728.640 ;
        RECT 3.990 725.240 969.850 727.240 ;
        RECT 3.990 723.840 969.450 725.240 ;
        RECT 3.990 721.840 969.850 723.840 ;
        RECT 3.990 720.440 969.450 721.840 ;
        RECT 3.990 718.440 969.850 720.440 ;
        RECT 3.990 717.040 969.450 718.440 ;
        RECT 3.990 715.040 969.850 717.040 ;
        RECT 3.990 713.640 969.450 715.040 ;
        RECT 3.990 711.640 969.850 713.640 ;
        RECT 4.400 710.240 969.450 711.640 ;
        RECT 3.990 708.240 969.850 710.240 ;
        RECT 4.400 706.840 969.450 708.240 ;
        RECT 3.990 704.840 969.850 706.840 ;
        RECT 4.400 703.440 969.450 704.840 ;
        RECT 3.990 701.440 969.850 703.440 ;
        RECT 4.400 700.040 969.450 701.440 ;
        RECT 3.990 698.040 969.850 700.040 ;
        RECT 3.990 696.640 969.450 698.040 ;
        RECT 3.990 694.640 969.850 696.640 ;
        RECT 4.400 693.240 969.450 694.640 ;
        RECT 3.990 691.240 969.850 693.240 ;
        RECT 4.400 689.840 969.450 691.240 ;
        RECT 3.990 687.840 969.850 689.840 ;
        RECT 4.400 686.440 969.450 687.840 ;
        RECT 3.990 684.440 969.850 686.440 ;
        RECT 4.400 683.040 969.450 684.440 ;
        RECT 3.990 681.040 969.850 683.040 ;
        RECT 3.990 679.640 969.450 681.040 ;
        RECT 3.990 674.240 969.850 679.640 ;
        RECT 4.400 672.840 969.850 674.240 ;
        RECT 3.990 653.840 969.850 672.840 ;
        RECT 4.400 652.440 969.850 653.840 ;
        RECT 3.990 650.440 969.850 652.440 ;
        RECT 4.400 649.040 969.850 650.440 ;
        RECT 3.990 647.040 969.850 649.040 ;
        RECT 4.400 645.640 969.850 647.040 ;
        RECT 3.990 643.640 969.850 645.640 ;
        RECT 4.400 642.240 969.850 643.640 ;
        RECT 3.990 640.240 969.850 642.240 ;
        RECT 4.400 638.840 969.850 640.240 ;
        RECT 3.990 636.840 969.850 638.840 ;
        RECT 4.400 635.440 969.850 636.840 ;
        RECT 3.990 633.440 969.850 635.440 ;
        RECT 4.400 632.040 969.850 633.440 ;
        RECT 3.990 630.040 969.850 632.040 ;
        RECT 4.400 628.640 969.850 630.040 ;
        RECT 3.990 626.640 969.850 628.640 ;
        RECT 4.400 625.240 969.850 626.640 ;
        RECT 3.990 623.240 969.850 625.240 ;
        RECT 4.400 621.840 969.850 623.240 ;
        RECT 3.990 619.840 969.850 621.840 ;
        RECT 4.400 618.440 969.450 619.840 ;
        RECT 3.990 616.440 969.850 618.440 ;
        RECT 3.990 615.040 969.450 616.440 ;
        RECT 3.990 613.040 969.850 615.040 ;
        RECT 3.990 611.640 969.450 613.040 ;
        RECT 3.990 609.640 969.850 611.640 ;
        RECT 4.400 608.240 969.450 609.640 ;
        RECT 3.990 606.240 969.850 608.240 ;
        RECT 4.400 604.840 969.450 606.240 ;
        RECT 3.990 602.840 969.850 604.840 ;
        RECT 4.400 601.440 969.450 602.840 ;
        RECT 3.990 599.440 969.850 601.440 ;
        RECT 4.400 598.040 969.450 599.440 ;
        RECT 3.990 596.040 969.850 598.040 ;
        RECT 3.990 594.640 969.450 596.040 ;
        RECT 3.990 592.640 969.850 594.640 ;
        RECT 4.400 591.240 969.450 592.640 ;
        RECT 3.990 589.240 969.850 591.240 ;
        RECT 4.400 587.840 969.450 589.240 ;
        RECT 3.990 585.840 969.850 587.840 ;
        RECT 4.400 584.440 969.450 585.840 ;
        RECT 3.990 582.440 969.850 584.440 ;
        RECT 4.400 581.040 969.450 582.440 ;
        RECT 3.990 579.040 969.850 581.040 ;
        RECT 3.990 577.640 969.450 579.040 ;
        RECT 3.990 575.640 969.850 577.640 ;
        RECT 4.400 574.240 969.450 575.640 ;
        RECT 3.990 572.240 969.850 574.240 ;
        RECT 4.400 570.840 969.450 572.240 ;
        RECT 3.990 568.840 969.850 570.840 ;
        RECT 4.400 567.440 969.450 568.840 ;
        RECT 3.990 565.440 969.850 567.440 ;
        RECT 4.400 564.040 969.450 565.440 ;
        RECT 3.990 562.040 969.850 564.040 ;
        RECT 4.400 560.640 969.450 562.040 ;
        RECT 3.990 558.640 969.850 560.640 ;
        RECT 3.990 557.240 969.450 558.640 ;
        RECT 3.990 555.240 969.850 557.240 ;
        RECT 3.990 553.840 969.450 555.240 ;
        RECT 3.990 551.840 969.850 553.840 ;
        RECT 3.990 550.440 969.450 551.840 ;
        RECT 3.990 548.440 969.850 550.440 ;
        RECT 4.400 547.040 969.450 548.440 ;
        RECT 3.990 545.040 969.850 547.040 ;
        RECT 4.400 543.640 969.450 545.040 ;
        RECT 3.990 541.640 969.850 543.640 ;
        RECT 4.400 540.240 969.450 541.640 ;
        RECT 3.990 538.240 969.850 540.240 ;
        RECT 4.400 536.840 969.450 538.240 ;
        RECT 3.990 534.840 969.850 536.840 ;
        RECT 4.400 533.440 969.450 534.840 ;
        RECT 3.990 531.440 969.850 533.440 ;
        RECT 3.990 530.040 969.450 531.440 ;
        RECT 3.990 528.040 969.850 530.040 ;
        RECT 3.990 526.640 969.450 528.040 ;
        RECT 3.990 524.640 969.850 526.640 ;
        RECT 3.990 523.240 969.450 524.640 ;
        RECT 3.990 521.240 969.850 523.240 ;
        RECT 3.990 519.840 969.450 521.240 ;
        RECT 3.990 517.840 969.850 519.840 ;
        RECT 4.400 516.440 969.450 517.840 ;
        RECT 3.990 514.440 969.850 516.440 ;
        RECT 4.400 513.040 969.450 514.440 ;
        RECT 3.990 511.040 969.850 513.040 ;
        RECT 4.400 509.640 969.450 511.040 ;
        RECT 3.990 507.640 969.850 509.640 ;
        RECT 4.400 506.240 969.450 507.640 ;
        RECT 3.990 504.240 969.850 506.240 ;
        RECT 4.400 502.840 969.450 504.240 ;
        RECT 3.990 500.840 969.850 502.840 ;
        RECT 3.990 499.440 969.450 500.840 ;
        RECT 3.990 497.440 969.850 499.440 ;
        RECT 4.400 496.040 969.450 497.440 ;
        RECT 3.990 494.040 969.850 496.040 ;
        RECT 4.400 492.640 969.450 494.040 ;
        RECT 3.990 490.640 969.850 492.640 ;
        RECT 3.990 489.240 969.450 490.640 ;
        RECT 3.990 487.240 969.850 489.240 ;
        RECT 3.990 485.840 969.450 487.240 ;
        RECT 3.990 483.840 969.850 485.840 ;
        RECT 3.990 482.440 969.450 483.840 ;
        RECT 3.990 480.440 969.850 482.440 ;
        RECT 3.990 479.040 969.450 480.440 ;
        RECT 3.990 477.040 969.850 479.040 ;
        RECT 3.990 475.640 969.450 477.040 ;
        RECT 3.990 473.640 969.850 475.640 ;
        RECT 3.990 472.240 969.450 473.640 ;
        RECT 3.990 470.240 969.850 472.240 ;
        RECT 3.990 468.840 969.450 470.240 ;
        RECT 3.990 466.840 969.850 468.840 ;
        RECT 3.990 465.440 969.450 466.840 ;
        RECT 3.990 463.440 969.850 465.440 ;
        RECT 3.990 462.040 969.450 463.440 ;
        RECT 3.990 460.040 969.850 462.040 ;
        RECT 3.990 458.640 969.450 460.040 ;
        RECT 3.990 456.640 969.850 458.640 ;
        RECT 3.990 455.240 969.450 456.640 ;
        RECT 3.990 453.240 969.850 455.240 ;
        RECT 3.990 451.840 969.450 453.240 ;
        RECT 3.990 449.840 969.850 451.840 ;
        RECT 3.990 448.440 969.450 449.840 ;
        RECT 3.990 446.440 969.850 448.440 ;
        RECT 3.990 445.040 969.450 446.440 ;
        RECT 3.990 443.040 969.850 445.040 ;
        RECT 3.990 441.640 969.450 443.040 ;
        RECT 3.990 439.640 969.850 441.640 ;
        RECT 3.990 438.240 969.450 439.640 ;
        RECT 3.990 436.240 969.850 438.240 ;
        RECT 3.990 434.840 969.450 436.240 ;
        RECT 3.990 432.840 969.850 434.840 ;
        RECT 3.990 431.440 969.450 432.840 ;
        RECT 3.990 429.440 969.850 431.440 ;
        RECT 3.990 428.040 969.450 429.440 ;
        RECT 3.990 426.040 969.850 428.040 ;
        RECT 3.990 424.640 969.450 426.040 ;
        RECT 3.990 422.640 969.850 424.640 ;
        RECT 3.990 421.240 969.450 422.640 ;
        RECT 3.990 419.240 969.850 421.240 ;
        RECT 3.990 417.840 969.450 419.240 ;
        RECT 3.990 415.840 969.850 417.840 ;
        RECT 3.990 414.440 969.450 415.840 ;
        RECT 3.990 412.440 969.850 414.440 ;
        RECT 3.990 411.040 969.450 412.440 ;
        RECT 3.990 409.040 969.850 411.040 ;
        RECT 3.990 407.640 969.450 409.040 ;
        RECT 3.990 405.640 969.850 407.640 ;
        RECT 3.990 404.240 969.450 405.640 ;
        RECT 3.990 402.240 969.850 404.240 ;
        RECT 3.990 400.840 969.450 402.240 ;
        RECT 3.990 398.840 969.850 400.840 ;
        RECT 3.990 397.440 969.450 398.840 ;
        RECT 3.990 395.440 969.850 397.440 ;
        RECT 3.990 394.040 969.450 395.440 ;
        RECT 3.990 392.040 969.850 394.040 ;
        RECT 3.990 390.640 969.450 392.040 ;
        RECT 3.990 388.640 969.850 390.640 ;
        RECT 3.990 387.240 969.450 388.640 ;
        RECT 3.990 385.240 969.850 387.240 ;
        RECT 3.990 383.840 969.450 385.240 ;
        RECT 3.990 381.840 969.850 383.840 ;
        RECT 3.990 380.440 969.450 381.840 ;
        RECT 3.990 378.440 969.850 380.440 ;
        RECT 3.990 377.040 969.450 378.440 ;
        RECT 3.990 375.040 969.850 377.040 ;
        RECT 3.990 373.640 969.450 375.040 ;
        RECT 3.990 371.640 969.850 373.640 ;
        RECT 3.990 370.240 969.450 371.640 ;
        RECT 3.990 368.240 969.850 370.240 ;
        RECT 3.990 366.840 969.450 368.240 ;
        RECT 3.990 364.840 969.850 366.840 ;
        RECT 3.990 363.440 969.450 364.840 ;
        RECT 3.990 361.440 969.850 363.440 ;
        RECT 3.990 360.040 969.450 361.440 ;
        RECT 3.990 358.040 969.850 360.040 ;
        RECT 3.990 356.640 969.450 358.040 ;
        RECT 3.990 354.640 969.850 356.640 ;
        RECT 3.990 353.240 969.450 354.640 ;
        RECT 3.990 351.240 969.850 353.240 ;
        RECT 3.990 349.840 969.450 351.240 ;
        RECT 3.990 347.840 969.850 349.840 ;
        RECT 3.990 346.440 969.450 347.840 ;
        RECT 3.990 344.440 969.850 346.440 ;
        RECT 3.990 343.040 969.450 344.440 ;
        RECT 3.990 341.040 969.850 343.040 ;
        RECT 3.990 339.640 969.450 341.040 ;
        RECT 3.990 337.640 969.850 339.640 ;
        RECT 3.990 336.240 969.450 337.640 ;
        RECT 3.990 334.240 969.850 336.240 ;
        RECT 3.990 332.840 969.450 334.240 ;
        RECT 3.990 330.840 969.850 332.840 ;
        RECT 3.990 329.440 969.450 330.840 ;
        RECT 3.990 327.440 969.850 329.440 ;
        RECT 3.990 326.040 969.450 327.440 ;
        RECT 3.990 324.040 969.850 326.040 ;
        RECT 3.990 322.640 969.450 324.040 ;
        RECT 3.990 320.640 969.850 322.640 ;
        RECT 3.990 319.240 969.450 320.640 ;
        RECT 3.990 317.240 969.850 319.240 ;
        RECT 3.990 315.840 969.450 317.240 ;
        RECT 3.990 313.840 969.850 315.840 ;
        RECT 3.990 312.440 969.450 313.840 ;
        RECT 3.990 310.440 969.850 312.440 ;
        RECT 3.990 309.040 969.450 310.440 ;
        RECT 3.990 307.040 969.850 309.040 ;
        RECT 3.990 305.640 969.450 307.040 ;
        RECT 3.990 303.640 969.850 305.640 ;
        RECT 3.990 302.240 969.450 303.640 ;
        RECT 3.990 300.240 969.850 302.240 ;
        RECT 3.990 298.840 969.450 300.240 ;
        RECT 3.990 296.840 969.850 298.840 ;
        RECT 3.990 295.440 969.450 296.840 ;
        RECT 3.990 293.440 969.850 295.440 ;
        RECT 3.990 292.040 969.450 293.440 ;
        RECT 3.990 290.040 969.850 292.040 ;
        RECT 3.990 288.640 969.450 290.040 ;
        RECT 3.990 286.640 969.850 288.640 ;
        RECT 3.990 285.240 969.450 286.640 ;
        RECT 3.990 283.240 969.850 285.240 ;
        RECT 3.990 281.840 969.450 283.240 ;
        RECT 3.990 279.840 969.850 281.840 ;
        RECT 3.990 278.440 969.450 279.840 ;
        RECT 3.990 276.440 969.850 278.440 ;
        RECT 3.990 275.040 969.450 276.440 ;
        RECT 3.990 273.040 969.850 275.040 ;
        RECT 3.990 271.640 969.450 273.040 ;
        RECT 3.990 9.015 969.850 271.640 ;
      LAYER met4 ;
        RECT 8.150 10.240 20.640 970.185 ;
        RECT 23.040 10.240 23.940 970.185 ;
        RECT 26.340 10.240 174.240 970.185 ;
        RECT 176.640 10.240 177.540 970.185 ;
        RECT 179.940 10.240 327.840 970.185 ;
        RECT 330.240 10.240 331.140 970.185 ;
        RECT 333.540 10.240 481.440 970.185 ;
        RECT 483.840 10.240 484.740 970.185 ;
        RECT 487.140 10.240 635.040 970.185 ;
        RECT 637.440 10.240 638.340 970.185 ;
        RECT 640.740 10.240 788.640 970.185 ;
        RECT 791.040 10.240 791.940 970.185 ;
        RECT 794.340 10.240 942.240 970.185 ;
        RECT 944.640 10.240 945.540 970.185 ;
        RECT 947.940 10.240 965.705 970.185 ;
        RECT 8.150 9.015 965.705 10.240 ;
      LAYER met5 ;
        RECT 7.940 645.950 680.220 733.500 ;
        RECT 7.940 492.770 680.220 637.850 ;
        RECT 7.940 339.590 680.220 484.670 ;
        RECT 7.940 186.410 680.220 331.490 ;
        RECT 7.940 160.700 680.220 178.310 ;
  END
END rv32i_core
END LIBRARY

